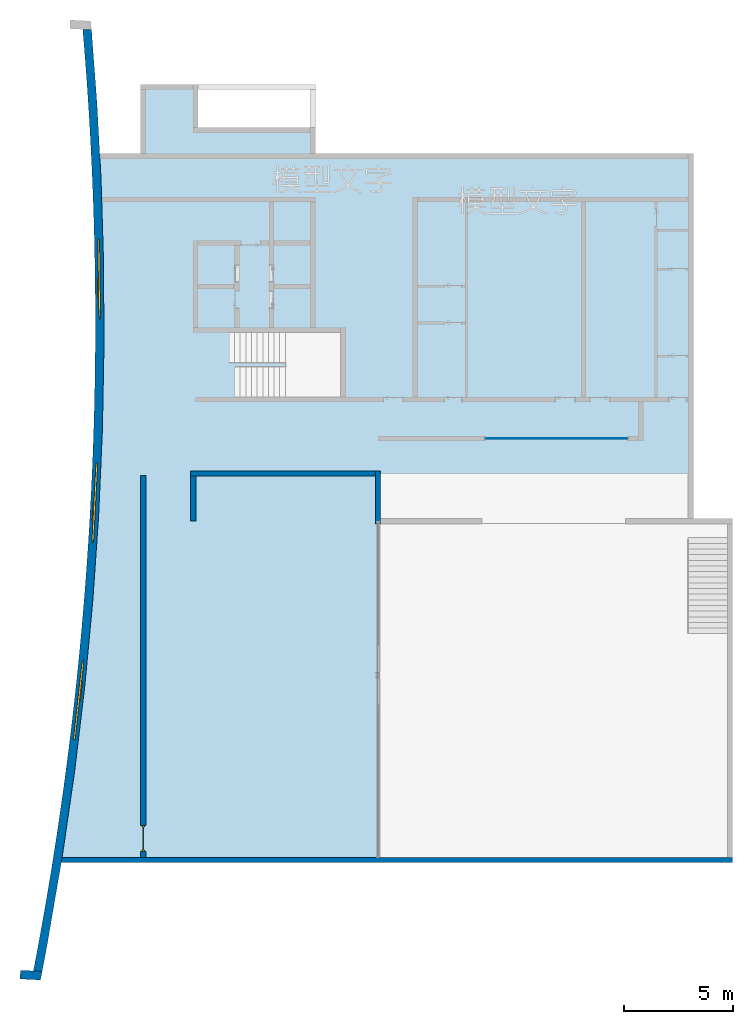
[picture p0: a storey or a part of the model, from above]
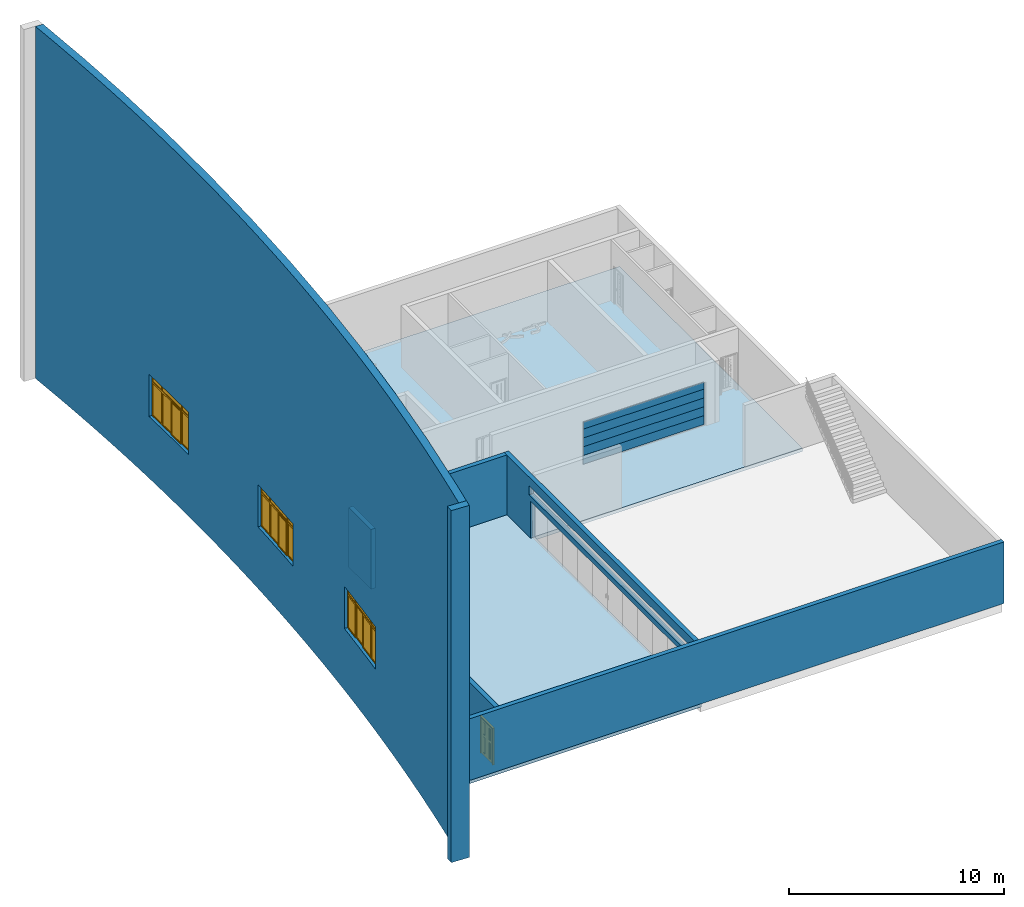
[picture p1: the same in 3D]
Properties of the parts of a building model (IFC2X3), part 1 of 2

# File
Description: ViewDefinition [CoordinationView_V2.0]
File name: 项目编号
Time: 2021-07-08T13:14:33
Written by: The EXPRESS Data Manager Version 5.02.0100.07 : 28 Aug 2013
Made in: 20180216_1515(x64) - Exporter 19.0.0.405 - 备用 UI 19.0.0.405
Comment: STEP Physical File produced by: The EXPRESS Data Manager Version 5.02.0100.07 : 28 Aug 2013 * Module: EDMstepFileFactory/EDMstandAlone * Creation date: Thu Jul 08 13:14:33 2021 * Host: DESKTOP-OMQ10H7 * Database: C:\Users\12580\AppData\Local\Temp\{74D62C54-28BB-4BCD-B5E0-11592904E337}\ifc * Database version: 5507 * Database creation date: Thu Jul 08 13:13:54 2021 * Schema: IFC2X3 * Model: DataRepository.ifc * Model creation date: Thu Jul 08 13:13:54 2021 * Header model: DataRepository.ifc_HeaderModel * Header model creation date: Thu Jul 08 13:13:54 2021 * EDMuser: sdai-user * EDMgroup: sdai-group * License ID and type: 5605 : Permanent license. Expiry date: * EDMstepFileFactory options: 020000

# IfcProject, 项目编号
LongName: 项目名称; Phase: 项目状态

# IfcSite, 表面:545270
RefLatitude: 42, 23, 13, 199999; RefLongitude: -71, -14, -31, -199999; RefElevation: 0 mm

# IfcBuilding
Pset_BuildingCommon - NumberOfStoreys: 6

# IfcBuildingStorey (6)
Name | LongName | Elevation (mm)
-1F | -1F | -3500
室外地坪 | 室外地坪 | -450
1F | 1F | 0
2F | 2F | 3000
3F | 3F | 6000
4F | 4F | 9000

# IfcBuildingElementProxy: 1 (2)
In: 1F
Type - Material: 默认体量
Pset_BuildingElementProxyCommon - Reference: 1
Name
1:1:349102
4:1:356210

# IfcBuildingElementProxy: 1800 mm (41)
Material: 木质 - 柚木, 金属 - 油漆面层 - 深灰色，粗面
Pset_BuildingElementProxyCommon - Reference: 1800 mm
Name (长椅:1800 mm:...) | In | Group
541240 | 1F | 模型组:长椅:541651
541490 | 1F | 模型组:长椅:541651
541573 | 1F | 模型组:长椅:541651
541606 | 1F | 模型组:长椅:541651
541667 | 1F | 模型组:长椅:541671
541668 | 1F | 模型组:长椅:541671
541669 | 1F | 模型组:长椅:541671
541670 | 1F | 模型组:长椅:541671
541781 | 1F | 模型组:长椅:541785
541782 | 1F | 模型组:长椅:541785
541783 | 1F | 模型组:长椅:541785
541784 | 1F | 模型组:长椅:541785
541787 | 1F | 模型组:长椅:541791
541788 | 1F | 模型组:长椅:541791
541789 | 1F | 模型组:长椅:541791
541790 | 1F | 模型组:长椅:541791
541793 | 1F | 模型组:长椅:541797
541794 | 1F | 模型组:长椅:541797
541795 | 1F | 模型组:长椅:541797
541796 | 1F | 模型组:长椅:541797
541799 | 1F | 模型组:长椅:541803
541800 | 1F | 模型组:长椅:541803
541801 | 1F | 模型组:长椅:541803
541802 | 1F | 模型组:长椅:541803
541805 | 1F | 模型组:长椅:541809
541806 | 1F | 模型组:长椅:541809
541807 | 1F | 模型组:长椅:541809
541808 | 1F | 模型组:长椅:541809
541811 | 1F | 模型组:长椅:541815
541812 | 1F | 模型组:长椅:541815
541813 | 1F | 模型组:长椅:541815
541814 | 1F | 模型组:长椅:541815
541817 | 1F | 模型组:长椅:541821
541818 | 1F | 模型组:长椅:541821
541819 | 1F | 模型组:长椅:541821
541820 | 1F | 模型组:长椅:541821
541823 | 1F | 模型组:长椅:541827
541824 | 1F | 模型组:长椅:541827
541825 | 1F | 模型组:长椅:541827
541826 | 1F | 模型组:长椅:541827
547560 | 室外地坪

# IfcBuildingElementProxy: 2 (2)
In: 1F
Type - Material: 默认体量
Pset_BuildingElementProxyCommon - Reference: 2
Name
2:2:351852
5:2:357694

# IfcBuildingElementProxy: 3 (2)
In: 1F
Type - Material: 默认体量
Pset_BuildingElementProxyCommon - Reference: 3
Name
3:3:354207
6:3:358945

# IfcBuildingElementProxy: Alex (3)
In: 室外地坪
Pset_BuildingElementProxyCommon - Reference: Alex
Name (RPC 男性:Alex:...)
560207
560258
560286

# IfcBuildingElementProxy: Cathy, RPC 女性:Cathy:559751
In: 室外地坪
Pset_BuildingElementProxyCommon - Reference: Cathy

# IfcBuildingElementProxy: RPC 甲虫, RPC 甲虫:RPC 甲虫:559956
In: 室外地坪
Pset_BuildingElementProxyCommon - Reference: RPC 甲虫

# IfcBuildingElementProxy: 中部体量, 中部体量:中部体量:361719
In: 1F
Type - Material: 默认体量
Pset_BuildingElementProxyCommon - Reference: 中部体量

# IfcBuildingElementProxy: 佛罗伦萨 (3)
In: 室外地坪
Pset_BuildingElementProxyCommon - Reference: 佛罗伦萨
Name (RPC 女性:佛罗伦萨:...)
559883
559900
559914

# IfcBuildingElementProxy: 公园长椅 2, 公园长椅 2:公园长椅 2:557213
In: 室外地坪
Material: 木质座椅, 预制混凝土
Pset_BuildingElementProxyCommon - Reference: 公园长椅 2

# IfcBuildingElementProxy: 北部体量, 北部体量:北部体量:362551
In: 1F
Type - Material: 默认体量
Pset_BuildingElementProxyCommon - Reference: 北部体量

# IfcBuildingElementProxy: 模型文字:600mm Arial (3)
Pset_BuildingElementProxyCommon - Reference: 600mm Arial
Name (模型文字:...) | In
2 x 600mm Arial | -1F
600mm Arial | 2F

# IfcBuildingElementProxy: 混凝土卡车 (2)
In: 室外地坪
Material: 金属-钢, 塑料 - 黑色, 金属 - 铬板, 金属 - 油漆面层 - 白色，粗面
Pset_BuildingElementProxyCommon - Reference: 混凝土卡车
Name (混凝土卡车:混凝土卡车:...)
549684
560604

# IfcColumn: 300 x 300mm (2)
In: 1F
Type - ElementType: 300 x 300mm; PredefinedType: COLUMN
Material: 柱
Pset_ColumnCommon - LoadBearing: no; IsExternal: no; Reference: 300 x 300mm; Slope: 0 deg
Name (矩形柱:300 x 300mm:...)
490802
491124

# IfcCurtainWall: 幕墙:幕墙 1 (9)
Pset_CurtainWallCommon - IsExternal: yes; Reference: 幕墙 1
Name (幕墙:幕墙 1:...) | In
402175 | 1F
402436 | 1F
407601 | 2F
407627 | 2F
427601 | 3F
432666 | 1F
434830 | -1F
437507 | -1F
528400 | 4F

# IfcCurtainWall: 幕墙:幕墙 2 (10)
Pset_CurtainWallCommon - IsExternal: yes; Reference: 幕墙 2
Name (幕墙:幕墙 2:...) | In
402656 | 1F
402850 | 1F
403013 | 1F
407659 | 3F
407665 | 3F
408702 | 2F
434038 | 1F
438280 | 2F
439420 | 3F
439495 | 3F

# IfcCurtainWall: 幕墙:幕墙 4 (8)
Pset_CurtainWallCommon - IsExternal: no; Reference: 幕墙 4
Name (幕墙:幕墙 4:...) | In
427907 | 3F
428382 | 3F
428785 | 3F
429204 | 3F
429508 | 3F
429925 | 2F
430066 | 2F
430233 | 2F

# IfcCurtainWall: 幕墙:幕墙 5, 幕墙:幕墙 5:432943
In: 1F
Pset_CurtainWallCommon - IsExternal: yes; Reference: 幕墙 5

# IfcCurtainWall: 幕墙:店面 (2)
Pset_CurtainWallCommon - IsExternal: yes; Reference: 店面
Name (幕墙:店面:...) | In
420110 | 3F
437167 | -1F

# IfcCurtainWall: 幕墙系统:1450 x 2100mm (6)
Pset_CurtainWallCommon - Reference: 1450 x 2100mm; IsExternal: no
Name (幕墙系统:1450 x 2100mm:...) | In
362911 | 1F
370759 | 1F
370957 | 1F
470212 | 1F
471675 | 1F
473225 | 3F

# IfcCurtainWall: 幕墙系统:1700 x 2100mm, 幕墙系统:1700 x 2100mm:366782
In: 3F
Pset_CurtainWallCommon - IsExternal: no; Reference: 1700 x 2100mm

# IfcDoor: 1200 x 2100 mm, 门-双扇平开:1200 x 2100 mm:384247
In: -1F
Type - OperationType: DOUBLE_DOOR_SINGLE_SWING; ParameterTakesPrecedence: no; Sizeable: no
Type - 门-双扇平开:1200 x 2100 mm:384247 - PanelOperation: SWINGING
OverallHeight: 2100 mm; OverallWidth: 1200 mm
Pset_DoorCommon - IsExternal: no; Reference: 1200 x 2100 mm

# IfcDoor: M0821 (26)
Type - ParameterTakesPrecedence: no; Sizeable: no; Material: 不锈钢, 门框材质, 门套材质, 门板材质
OverallHeight: 2100 mm; OverallWidth: 800 mm
Pset_DoorCommon - IsExternal: no; Reference: M0821
Name (装饰木门:M0821:...) | In
382676 | -1F
382819 | -1F
383177 | -1F
383178 | -1F
383197 | -1F
383379 | -1F
383451 | -1F
383554 | -1F
383631 | -1F
383688 | -1F
383731 | -1F
396554 | 1F
396845 | 1F
396930 | 1F
396993 | 1F
397054 | 1F
407593 | 2F
407594 | 2F
407595 | 2F
407596 | 2F
407597 | 2F
425033 | 3F
425121 | 3F
425207 | 3F
425580 | 3F
425584 | 3F

# IfcDoor: M0921 (16)
Type - ParameterTakesPrecedence: no; Sizeable: no; Material: 门锁－不锈钢, 门框材质, 门套材质, 门板材质
OverallHeight: 2100 mm; OverallWidth: 900 mm
Pset_DoorCommon - IsExternal: no; Reference: M0921
Name (装饰木门:M0921:...) | In
382155 | -1F
382442 | -1F
383980 | -1F
384059 | -1F
396196 | 1F
396287 | 1F
397109 | 1F
397167 | 1F
397294 | 1F
397396 | 1F
407598 | 2F
407599 | 2F
424080 | 3F
424512 | 3F
424859 | 3F
424940 | 3F

# IfcDoor: YM3267 (3)
In: 1F
Type - ParameterTakesPrecedence: no; Sizeable: no; Material: 玻璃, 铝合金
OverallHeight: 2400 mm; OverallWidth: 1800 mm
Pset_DoorCommon - IsExternal: no; Reference: YM3267
Name (YM1824:YM3267:...)
493118
493990
494000

# IfcDoor: YM3624 (6)
In: 1F
Type - ParameterTakesPrecedence: no; Sizeable: no; Material: 铝合金, 玻璃
OverallHeight: 2400 mm; OverallWidth: 3600 mm
Pset_DoorCommon - IsExternal: no; Reference: YM3624
Name (YM3627:YM3624:...)
495469
495638
495714
495795
495809
495830

# IfcDoor: 幕墙单开玻璃门 900/2100 (2)
In: 3F
Type - OperationType: SINGLE_SWING_LEFT; ParameterTakesPrecedence: no; Sizeable: no; Material: 金属 - 铝, 玻璃
Type - 幕墙单开玻璃门:幕墙单开玻璃门 900/2100:428383 - PanelOperation: SWINGING
OverallHeight: 2050 mm; OverallWidth: 1400 mm
Pset_DoorCommon - IsExternal: no; Reference: 幕墙单开玻璃门 900/2100
Name (幕墙单开玻璃门:幕墙单开玻璃门 900/2100:...)
428383
429509

# IfcDoor: 幕墙单开玻璃门 900/2100, 幕墙单开玻璃门:幕墙单开玻璃门 900/2100:428786
In: 3F
Type - OperationType: SINGLE_SWING_LEFT; ParameterTakesPrecedence: no; Sizeable: no; Material: 金属 - 铝, 玻璃
Type - 幕墙单开玻璃门:幕墙单开玻璃门 900/2100:428786 - PanelOperation: SWINGING
OverallHeight: 2050 mm; OverallWidth: 1100 mm
Pset_DoorCommon - IsExternal: no; Reference: 幕墙单开玻璃门 900/2100

# IfcDoor: 幕墙单开玻璃门 900/2100, 幕墙单开玻璃门:幕墙单开玻璃门 900/2100:438494
In: 2F
Type - OperationType: SINGLE_SWING_LEFT; ParameterTakesPrecedence: no; Sizeable: no; Material: 金属 - 铝, 玻璃
Type - 幕墙单开玻璃门:幕墙单开玻璃门 900/2100:438494 - PanelOperation: SWINGING
OverallHeight: 2550 mm; OverallWidth: 1225 mm
Pset_DoorCommon - IsExternal: no; Reference: 幕墙单开玻璃门 900/2100

# IfcDoor: 幕墙单开玻璃门 900/2100, 幕墙单开玻璃门:幕墙单开玻璃门 900/2100:439426
In: 3F
Type - OperationType: SINGLE_SWING_LEFT; ParameterTakesPrecedence: no; Sizeable: no; Material: 金属 - 铝, 玻璃
Type - 幕墙单开玻璃门:幕墙单开玻璃门 900/2100:439426 - PanelOperation: SWINGING
OverallHeight: 2550 mm; OverallWidth: 1185 mm
Pset_DoorCommon - IsExternal: no; Reference: 幕墙单开玻璃门 900/2100

# IfcDoor: 幕墙单开玻璃门 900/2100, 幕墙单开玻璃门:幕墙单开玻璃门 900/2100:471819
In: 1F
Type - OperationType: SINGLE_SWING_LEFT; ParameterTakesPrecedence: no; Sizeable: no; Material: 金属 - 铝, 玻璃
Type - 幕墙单开玻璃门:幕墙单开玻璃门 900/2100:471819 - PanelOperation: SWINGING
OverallHeight: 1925 mm; OverallWidth: 1400 mm
Pset_DoorCommon - IsExternal: no; Reference: 幕墙单开玻璃门 900/2100

# IfcDoor: 幕墙单开玻璃门 900/2100, 幕墙单开玻璃门:幕墙单开玻璃门 900/2100:563182
In: -1F
Type - OperationType: SINGLE_SWING_LEFT; ParameterTakesPrecedence: no; Sizeable: no; Material: 金属 - 铝, 玻璃
Type - 幕墙单开玻璃门:幕墙单开玻璃门 900/2100:563182 - PanelOperation: SWINGING
OverallHeight: 2050 mm; OverallWidth: 1396.36 mm
Pset_DoorCommon - IsExternal: no; Reference: 幕墙单开玻璃门 900/2100

# IfcDoor: 幕墙单开玻璃门 900/2100 (2)
In: 3F
Type - OperationType: SINGLE_SWING_RIGHT; ParameterTakesPrecedence: no; Sizeable: no; Material: 金属 - 铝, 玻璃
Type - 幕墙单开玻璃门:幕墙单开玻璃门 900/2100:427908 - PanelOperation: SWINGING
OverallHeight: 2050 mm; OverallWidth: 1100 mm
Pset_DoorCommon - IsExternal: no; Reference: 幕墙单开玻璃门 900/2100
Name (幕墙单开玻璃门:幕墙单开玻璃门 900/2100:...)
427908
429205

# IfcDoor: 幕墙单开玻璃门 900/2100, 幕墙单开玻璃门:幕墙单开玻璃门 900/2100:563180
In: -1F
Type - OperationType: SINGLE_SWING_RIGHT; ParameterTakesPrecedence: no; Sizeable: no; Material: 金属 - 铝, 玻璃
Type - 幕墙单开玻璃门:幕墙单开玻璃门 900/2100:563180 - PanelOperation: SWINGING
OverallHeight: 2050 mm; OverallWidth: 1396.36 mm
Pset_DoorCommon - IsExternal: no; Reference: 幕墙单开玻璃门 900/2100

# IfcDoor: 幕墙双开玻璃门 1800/2100 (3)
In: 1F
Type - OperationType: DOUBLE_DOOR_SINGLE_SWING; ParameterTakesPrecedence: no; Sizeable: no; Material: 金属 - 铝, 玻璃
Type - 幕墙双开玻璃门:幕墙双开玻璃门 1800/2100:362931 - PanelOperation: SWINGING
OverallHeight: 1926.86 mm; OverallWidth: 2850 mm
Pset_DoorCommon - IsExternal: no; Reference: 幕墙双开玻璃门 1800/2100
Name (幕墙双开玻璃门:幕墙双开玻璃门 1800/2100:...)
362931
470527
470531

# IfcDoor: 幕墙双开玻璃门 1800/2100, 幕墙双开玻璃门:幕墙双开玻璃门 1800/2100:407660
In: 3F
Type - OperationType: DOUBLE_DOOR_SINGLE_SWING; ParameterTakesPrecedence: no; Sizeable: no; Material: 金属 - 铝, 玻璃
Type - 幕墙双开玻璃门:幕墙双开玻璃门 1800/2100:407660 - PanelOperation: SWINGING
OverallHeight: 2651.86 mm; OverallWidth: 1745 mm
Pset_DoorCommon - IsExternal: no; Reference: 幕墙双开玻璃门 1800/2100

# IfcDoor: 幕墙双开玻璃门 1800/2100, 幕墙双开玻璃门:幕墙双开玻璃门 1800/2100:407666
In: 3F
Type - OperationType: DOUBLE_DOOR_SINGLE_SWING; ParameterTakesPrecedence: no; Sizeable: no; Material: 金属 - 铝, 玻璃
Type - 幕墙双开玻璃门:幕墙双开玻璃门 1800/2100:407666 - PanelOperation: SWINGING
OverallHeight: 2651.86 mm; OverallWidth: 2460 mm
Pset_DoorCommon - IsExternal: no; Reference: 幕墙双开玻璃门 1800/2100

# IfcDoor: 幕墙双开玻璃门 1800/2100, 幕墙双开玻璃门:幕墙双开玻璃门 1800/2100:434039
In: 1F
Type - OperationType: DOUBLE_DOOR_SINGLE_SWING; ParameterTakesPrecedence: no; Sizeable: no; Material: 金属 - 铝, 玻璃
Type - 幕墙双开玻璃门:幕墙双开玻璃门 1800/2100:434039 - PanelOperation: SWINGING
OverallHeight: 2551.86 mm; OverallWidth: 2180 mm
Pset_DoorCommon - IsExternal: no; Reference: 幕墙双开玻璃门 1800/2100

# IfcDoor: 幕墙双开玻璃门 1800/2100, 幕墙双开玻璃门:幕墙双开玻璃门 1800/2100:435355
In: 3F
Type - OperationType: DOUBLE_DOOR_SINGLE_SWING; ParameterTakesPrecedence: no; Sizeable: no; Material: 金属 - 铝, 玻璃
Type - 幕墙双开玻璃门:幕墙双开玻璃门 1800/2100:435355 - PanelOperation: SWINGING
OverallHeight: 2651.86 mm; OverallWidth: 2065 mm
Pset_DoorCommon - IsExternal: no; Reference: 幕墙双开玻璃门 1800/2100

# IfcDoor: 幕墙双开玻璃门 1800/2100, 幕墙双开玻璃门:幕墙双开玻璃门 1800/2100:530989
In: 3F
Type - OperationType: DOUBLE_DOOR_SINGLE_SWING; ParameterTakesPrecedence: no; Sizeable: no; Material: 金属 - 铝, 玻璃
Type - 幕墙双开玻璃门:幕墙双开玻璃门 1800/2100:530989 - PanelOperation: SWINGING
OverallHeight: 2376.86 mm; OverallWidth: 2580 mm
Pset_DoorCommon - IsExternal: no; Reference: 幕墙双开玻璃门 1800/2100

# IfcMember: 200 x 150mm (378)
Type - ElementType: 200 x 150mm; PredefinedType: MEMBER
Material: 木质 - 木材
Pset_MemberCommon - IsExternal: no; LoadBearing: yes; Reference: 200 x 150mm
Name (矩形竖梃:200 x 150mm:...) | In | Span (mm)
363015 | 1F | 971.063
363016 | 1F | 412.198
363017 | 1F | 1501.01
363018 | 1F | 1501.01
363019 | 1F | 2105.22
363020 | 1F | 2116.63
363021 | 1F | 2131
363022 | 1F | 2151.01
363023 | 1F | 127.533
363024 | 1F | 1054.05
363025 | 1F | 2100.82
363026 | 1F | 2107.41
363027 | 1F | 2120.79
363028 | 1F | 2141.35
363142 | 1F | 280
363143 | 1F | 1425
363144 | 1F | 1236.66
363145 | 1F | 202.271
480478 | 1F | 1425
480479 | 1F | 1236.66
363042 | 1F | 412.924
363043 | 1F | 1425
363044 | 1F | 527.766
363045 | 1F | 1501.01
363046 | 1F | 2101.27
363047 | 1F | 2111.51
363048 | 1F | 2132.46
363049 | 1F | 1211.51
363050 | 1F | 350.213
363051 | 1F | 2106.56
363052 | 1F | 2122.27
363053 | 1F | 2141.38
363164 | 1F | 1400
363165 | 1F | 1223.42
366785 | 3F | 628.845
366786 | 3F | 1513.49
366787 | 3F | 2102.69
366788 | 3F | 1018
366904 | 3F | 1906.11
366905 | 3F | 253.002
366906 | 3F | 1968.35
366907 | 3F | 1912.8
366908 | 3F | 1568.41
366909 | 3F | 1828.98
366910 | 3F | 1796.37
366911 | 3F | 844.641
366912 | 3F | 1748.78
366913 | 3F | 1732.03
366914 | 3F | 1786.38
366915 | 3F | 301.544
366916 | 3F | 928.231
366917 | 3F | 2082.13
366918 | 3F | 915.346
366919 | 3F | 1947.33
366920 | 3F | 1286.7
366921 | 3F | 1853.18
366922 | 3F | 1817.18
366923 | 3F | 1470.92
366924 | 3F | 1762.36
366925 | 3F | 1742.24
366926 | 3F | 413.468
366927 | 3F | 658.268
366928 | 3F | 1093.35
366929 | 3F | 609.558
366930 | 3F | 316.31
366931 | 3F | 1149.51
366932 | 3F | 1117.99
366933 | 3F | 2102.69
370762 | 1F | 813.114
370763 | 1F | 1164.71
370764 | 1F | 2100
370765 | 1F | 313.218
370790 | 1F | 813.114
370791 | 1F | 1164.71
370792 | 1F | 2100
370793 | 1F | 2100
370794 | 1F | 2100
370795 | 1F | 1546.41
370796 | 1F | 2100
370797 | 1F | 2100
370798 | 1F | 2100
370799 | 1F | 2100
370960 | 1F | 525.869
370961 | 1F | 277.654
370962 | 1F | 460.207
370963 | 1F | 2100
371001 | 1F | 1275
371003 | 1F | 1709.15
371005 | 1F | 2100
371006 | 1F | 2100
371007 | 1F | 2100
371008 | 1F | 1953.01
371009 | 1F | 460.207
371010 | 1F | 2100
371011 | 1F | 2100
371012 | 1F | 2100
371013 | 1F | 2100
371100 | 1F | 1400
371106 | 1F | 826.132
371258 | 1F | 1431.5
470223 | 1F | 900.327
470224 | 1F | 1720.07
470225 | 1F | 2102.07
470226 | 1F | 772.514
470978 | 1F | 1060.92
470979 | 1F | 1452.77
470980 | 1F | 1452.77
470981 | 1F | 1452.77
470982 | 1F | 1452.77
470983 | 1F | 1452.77
470984 | 1F | 1452.77
470985 | 1F | 1452.77
470986 | 1F | 1452.77
470987 | 1F | 1452.77
470988 | 1F | 1452.77
470989 | 1F | 1452.77
470990 | 1F | 1452.77
470991 | 1F | 1452.77
470992 | 1F | 1452.77
470993 | 1F | 1452.77
470994 | 1F | 1452.77
470995 | 1F | 1452.77
470996 | 1F | 1452.77
470997 | 1F | 1452.77
470998 | 1F | 1452.77
470999 | 1F | 1552.03
471000 | 1F | 1631.03
471001 | 1F | 1596.03
471002 | 1F | 1566.11
471003 | 1F | 103.6
471004 | 1F | 1518.94
471005 | 1F | 1500.74
471006 | 1F | 1485.67
471007 | 1F | 1473.48
471008 | 1F | 1378.06
471009 | 1F | 1456.98
471010 | 1F | 1452.43
471011 | 1F | 1450.23
471012 | 1F | 1450.36
471013 | 1F | 1452.82
471014 | 1F | 1380.29
471015 | 1F | 1464.9
471016 | 1F | 1474.71
471017 | 1F | 1487.21
471018 | 1F | 1502.61
471019 | 1F | 406.519
471020 | 1F | 119.992
471021 | 1F | 1437.01
471022 | 1F | 85.9248
471023 | 1F | 77.3687
471024 | 1F | 2102.07
471025 | 1F | 2102.07
471026 | 1F | 2102.07
471027 | 1F | 400.107
471028 | 1F | 187.068
471029 | 1F | 2102.07
471030 | 1F | 2102.07
471031 | 1F | 2102.07
471032 | 1F | 2102.07
471033 | 1F | 2102.07
470219 | 1F | 406.676
470220 | 1F | 1050.25
470221 | 1F | 2100
470222 | 1F | 805.488
470801 | 1F | 1275
470802 | 1F | 1400
470803 | 1F | 1425
470804 | 1F | 1425
470805 | 1F | 1425
470806 | 1F | 1425
470807 | 1F | 1400
470808 | 1F | 1400
470809 | 1F | 1400
470810 | 1F | 1400
470811 | 1F | 1709.15
470812 | 1F | 1598.73
470813 | 1F | 1709.15
470814 | 1F | 1709.15
470815 | 1F | 438.06
470816 | 1F | 1215.04
470817 | 1F | 658.896
470818 | 1F | 110.418
470819 | 1F | 1271.09
470820 | 1F | 2100
470821 | 1F | 2100
470822 | 1F | 2100
470823 | 1F | 2100
470824 | 1F | 1544
470825 | 1F | 726.09
470826 | 1F | 716.816
470827 | 1F | 1225.07
470828 | 1F | 2100.99
470829 | 1F | 2109
470830 | 1F | 900.467
470831 | 1F | 2150.44
470832 | 1F | 2185.42
470833 | 1F | 1515.08
470834 | 1F | 2291.18
470835 | 1F | 2352.8
470228 | 1F | 919.197
470229 | 1F | 1119.2
470230 | 1F | 92.6751
470231 | 1F | 2101.21
470232 | 1F | 2100
470233 | 1F | 530.201
470234 | 1F | 650
470761 | 1F | 330.803
470762 | 1F | 1400
470763 | 1F | 130.803
470764 | 1F | 1400
470765 | 1F | 1400
470766 | 1F | 1400
470767 | 1F | 1425
470768 | 1F | 1400
470769 | 1F | 1773.28
470771 | 1F | 1709.15
470772 | 1F | 623.011
470773 | 1F | 1709.15
470774 | 1F | 169.969
470775 | 1F | 1086.14
470776 | 1F | 1827.77
470777 | 1F | 1198.77
470778 | 1F | 1808.57
470779 | 1F | 2110.96
470780 | 1F | 2130.89
470781 | 1F | 2161.86
470782 | 1F | 1006.93
470783 | 1F | 2263.59
470784 | 1F | 531.709
470785 | 1F | 1140.14
470786 | 1F | 2100
470787 | 1F | 2100
470788 | 1F | 2100
470789 | 1F | 2100
470790 | 1F | 650
470791 | 1F | 2100
470792 | 1F | 2100
470793 | 1F | 2100
470794 | 1F | 2100
470795 | 1F | 2100
470796 | 1F | 2100
470797 | 1F | 2100
470798 | 1F | 2100
470799 | 1F | 2100
470800 | 1F | 2100
471690 | 1F | 94.8808
471691 | 1F | 1179.71
471692 | 1F | 2102.55
471693 | 1F | 576.865
471962 | 1F | 1529.01
471963 | 1F | 1690.04
471964 | 1F | 787.746
471965 | 1F | 1610.45
471966 | 1F | 1579.66
471967 | 1F | 291.576
471968 | 1F | 1529.13
471969 | 1F | 1511.27
471970 | 1F | 1495.34
471971 | 1F | 1482.37
471972 | 1F | 1472.14
471973 | 1F | 1464.5
471974 | 1F | 1459.33
471975 | 1F | 1456.56
471976 | 1F | 1456.14
471977 | 1F | 1456.65
471978 | 1F | 862.118
471979 | 1F | 1263.26
471980 | 1F | 1738.08
471981 | 1F | 1527.45
471982 | 1F | 1644.5
471983 | 1F | 1607.72
471984 | 1F | 1396.31
471985 | 1F | 1549.36
471986 | 1F | 1526.47
471987 | 1F | 1507.14
471988 | 1F | 1491.01
471989 | 1F | 1283.74
471990 | 1F | 1467.35
471991 | 1F | 1459.44
471992 | 1F | 1453.96
471993 | 1F | 1450.84
471994 | 1F | 1304.13
471995 | 1F | 618.239
471996 | 1F | 160.123
471997 | 1F | 179.98
471998 | 1F | 194.121
471999 | 1F | 1396.2
472000 | 1F | 1816.18
472001 | 1F | 107.448
472002 | 1F | 286.364
472003 | 1F | 2102.55
471686 | 1F | 675.136
471687 | 1F | 1542.81
471688 | 1F | 2105.29
471689 | 1F | 1169.29
472041 | 1F | 1400
472042 | 1F | 1400
472043 | 1F | 1400
472044 | 1F | 85.8522
472045 | 1F | 1542.81
472046 | 1F | 260.971
472047 | 1F | 1456.96
472048 | 1F | 2116.91
472049 | 1F | 2131.63
472050 | 1F | 2153.68
472051 | 1F | 1600.36
472052 | 1F | 814.638
472053 | 1F | 2100.88
472054 | 1F | 2107.93
472055 | 1F | 2122.26
472056 | 1F | 1329.9
472057 | 1F | 2174.82
471682 | 1F | 749.617
471684 | 1F | 2101.29
471685 | 1F | 1433.97
472004 | 1F | 1425
472005 | 1F | 1400
472006 | 1F | 1569.41
472007 | 1F | 212.275
472008 | 1F | 350.885
472009 | 1F | 1330.54
472010 | 1F | 2111.74
472011 | 1F | 2133.1
472012 | 1F | 2166.4
472013 | 1F | 648.889
472014 | 1F | 134.916
472015 | 1F | 2106.31
472016 | 1F | 2121.21
472017 | 1F | 2138.77
473228 | 3F | 670.971
473229 | 3F | 1452.55
473230 | 3F | 2102.07
473350 | 3F | 1321.57
473351 | 3F | 1400
473352 | 3F | 1400
473353 | 3F | 1400
473354 | 3F | 1400
473355 | 3F | 1400
473356 | 3F | 1400
473357 | 3F | 1400
473358 | 3F | 1400
473359 | 3F | 1400
473360 | 3F | 1400
473361 | 3F | 1400
473362 | 3F | 1400
473363 | 3F | 1400
473364 | 3F | 1400
473365 | 3F | 1400
473366 | 3F | 1400
473367 | 3F | 1400
473368 | 3F | 1400
473369 | 3F | 1400
473370 | 3F | 1400
473371 | 3F | 1452.68
473372 | 3F | 1452.17
473373 | 3F | 1451.82
473374 | 3F | 1451.65
473375 | 3F | 1451.65
473376 | 3F | 1451.82
473377 | 3F | 1452.15
473378 | 3F | 1452.67
473379 | 3F | 1453.35
473380 | 3F | 1454.2
473381 | 3F | 1455.23
473382 | 3F | 1456.42
473383 | 3F | 1457.8
473384 | 3F | 1459.34
473385 | 3F | 1461.07
473386 | 3F | 1462.97
473387 | 3F | 1465.04
473388 | 3F | 1467.3
473389 | 3F | 1469.74
473390 | 3F | 1472.03
473391 | 3F | 286.835
473392 | 3F | 229.366
473393 | 3F | 227.356
473394 | 3F | 2102.07
473395 | 3F | 2127.1

# IfcMember: 300x600 (16)
In: 1F
Type - ElementType: 300x600; PredefinedType: MEMBER
Material: 白色涂料
Pset_MemberCommon - IsExternal: yes; LoadBearing: yes; Reference: 300x600
Name (矩形竖梃:300x600:...) | Span (mm)
488811 | 5150
488812 | 1690
488813 | 1690
490039 | 5150
490212 | 1540
490213 | 1540
490214 | 1540
490215 | 1690
490217 | 1690
490218 | 1540
490219 | 1540
490220 | 1540
490237 | 5150
490241 | 5150
490245 | 5150
490249 | 5150

# IfcMember: 30mm 正方形 (5)
Type - ElementType: 30mm 正方形; PredefinedType: MEMBER
Material: 金属 - 铝
Pset_MemberCommon - IsExternal: yes; LoadBearing: yes; Reference: 30mm 正方形
Name (矩形竖梃:30mm 正方形:...) | In | Span (mm)
563247 | -1F | 2100
500285 | 1F | 900
500373 | 1F | 900
489527 | 1F | 900
489552 | 1F | 900

# IfcMember: 50 x 100mm (874)
Type - ElementType: 50 x 100mm; PredefinedType: MEMBER
Material: 金属 - 铝
Pset_MemberCommon - LoadBearing: yes; Reference: 50 x 100mm
Name (矩形竖梃:50 x 100mm:...) | In | IsExternal | Span (mm)
363029 | 1F | no | 472.865
363030 | 1F | no | 1400
363031 | 1F | no | 655.474
363033 | 1F | no | 961.892
363034 | 1F | no | 1400
363035 | 1F | no | 1395.33
363036 | 1F | no | 1400
363037 | 1F | no | 512.028
363038 | 1F | no | 2100
363039 | 1F | no | 2100
363040 | 1F | no | 2100
363041 | 1F | no | 2100
363146 | 1F | no | 1400
363147 | 1F | no | 912.372
363149 | 1F | no | 735.744
363150 | 1F | no | 1400
363151 | 1F | no | 439.493
363152 | 1F | no | 1400
363153 | 1F | no | 20.7201
363154 | 1F | no | 900.022
363155 | 1F | no | 197.036
363157 | 1F | no | 2100
363158 | 1F | no | 2125
363159 | 1F | no | 2100
363161 | 1F | no | 2100
363162 | 1F | no | 2125
363163 | 1F | no | 2100
480480 | 1F | no | 255
480482 | 1F | no | 255
480483 | 1F | no | 255
480596 | 1F | no | 900.022
480597 | 1F | no | 2125
480598 | 1F | no | 2100
480603 | 1F | no | 2100
480882 | 1F | no | 1400
480884 | 1F | no | 1400
363054 | 1F | no | 1351.95
363055 | 1F | no | 1400
363056 | 1F | no | 1131.74
363057 | 1F | no | 1400
363058 | 1F | no | 761.074
363059 | 1F | no | 1400
363060 | 1F | no | 1043.18
363061 | 1F | no | 2100
363062 | 1F | no | 2100
363063 | 1F | no | 2100
363166 | 1F | no | 486.525
363167 | 1F | no | 708.42
363168 | 1F | no | 1081.98
363169 | 1F | no | 655.181
363170 | 1F | no | 2100
363171 | 1F | no | 2100
363172 | 1F | no | 2100
366934 | 3F | no | 1616.88
366935 | 3F | no | 1463.43
366936 | 3F | no | 498.387
366937 | 3F | no | 1650
366938 | 3F | no | 1650
366939 | 3F | no | 1650
366940 | 3F | no | 244.094
366941 | 3F | no | 907.359
366942 | 3F | no | 1650
366943 | 3F | no | 1650
366944 | 3F | no | 1650
366945 | 3F | no | 1650
366946 | 3F | no | 862.393
366947 | 3F | no | 526.005
366948 | 3F | no | 1650
366949 | 3F | no | 1650
366950 | 3F | no | 1650
366951 | 3F | no | 1650
366952 | 3F | no | 1650
366953 | 3F | no | 538.625
366954 | 3F | no | 277.718
366955 | 3F | no | 1650
366956 | 3F | no | 1650
366957 | 3F | no | 432.319
366958 | 3F | no | 399.229
366959 | 3F | no | 1601.42
366960 | 3F | no | 571.069
366961 | 3F | no | 1520.85
366962 | 3F | no | 260.68
366963 | 3F | no | 998.437
366964 | 3F | no | 1640.43
366965 | 3F | no | 91.7251
366966 | 3F | no | 556.403
366967 | 3F | no | 937.706
366968 | 3F | no | 977.124
366969 | 3F | no | 2100
366970 | 3F | no | 1969.38
366971 | 3F | no | 989.661
366972 | 3F | no | 126.551
366973 | 3F | no | 2100
366974 | 3F | no | 2100
366975 | 3F | no | 1471.09
366976 | 3F | no | 816.186
366977 | 3F | no | 256.173
366978 | 3F | no | 2100
366979 | 3F | no | 2100
366980 | 3F | no | 2100
366981 | 3F | no | 1886.55
366982 | 3F | no | 1503.76
366983 | 3F | no | 1205.03
366984 | 3F | no | 2100
366985 | 3F | no | 2100
366986 | 3F | no | 2100
370800 | 1F | no | 813.114
370801 | 1F | no | 813.114
370802 | 1F | no | 813.114
370803 | 1F | no | 813.114
370804 | 1F | no | 813.114
370805 | 1F | no | 813.114
370806 | 1F | no | 813.114
370807 | 1F | no | 813.114
370808 | 1F | no | 929.814
370809 | 1F | no | 2100
370810 | 1F | no | 2100
370811 | 1F | no | 2100
370812 | 1F | no | 2100
371016 | 1F | no | 1400
371019 | 1F | no | 1400
371022 | 1F | no | 1400
371025 | 1F | no | 1400
371030 | 1F | no | 460.207
371032 | 1F | no | 2100
371034 | 1F | no | 2100
371036 | 1F | no | 2100
371082 | 1F | no | 757.83
371101 | 1F | no | 525.869
371102 | 1F | no | 525.869
371103 | 1F | no | 525.869
371104 | 1F | no | 525.869
371105 | 1F | no | 525.869
371108 | 1F | no | 460.207
371109 | 1F | no | 2100
371110 | 1F | no | 2100
371111 | 1F | no | 2100
371146 | 1F | no | 1275
371147 | 1F | no | 1275
371148 | 1F | no | 1275
371149 | 1F | no | 1275
371233 | 1F | no | 1400
371234 | 1F | no | 2100
371259 | 1F | no | 1662.65
371289 | 1F | no | 1189.45
371290 | 1F | no | 2100
435362 | 3F | yes | 2700
531047 | 3F | yes | 1290
531048 | 3F | yes | 1290
531049 | 3F | yes | 1290
427920 | 3F | no | 1100
428395 | 3F | no | 1400
428798 | 3F | no | 1100
429217 | 3F | no | 1100
429518 | 3F | no | 1400
429938 | 2F | no | 1900
430079 | 2F | no | 3200
430246 | 2F | no | 2100
432967 | 1F | yes | 1180
432968 | 1F | yes | 1180
432969 | 1F | yes | 1180
432970 | 1F | yes | 1180
438501 | 2F | yes | 900
438892 | 2F | yes | 1650
439428 | 3F | yes | 900
439434 | 3F | yes | 1650
471034 | 1F | no | 1127.24
471035 | 1F | no | 1400
471036 | 1F | no | 1400
471037 | 1F | no | 1400
471038 | 1F | no | 1400
471039 | 1F | no | 1400
471040 | 1F | no | 1400
471041 | 1F | no | 1400
471042 | 1F | no | 1400
471043 | 1F | no | 1400
471044 | 1F | no | 1400
471045 | 1F | no | 1400
471046 | 1F | no | 1400
471047 | 1F | no | 1400
471048 | 1F | no | 1400
471049 | 1F | no | 1400
471050 | 1F | no | 1400
471051 | 1F | no | 1400
471052 | 1F | no | 1400
471053 | 1F | no | 1400
471054 | 1F | no | 1400
471055 | 1F | no | 865.307
471056 | 1F | no | 1220.57
471057 | 1F | no | 1400
471058 | 1F | no | 1400
471059 | 1F | no | 1400
471060 | 1F | no | 1400
471061 | 1F | no | 1400
471062 | 1F | no | 1400
471063 | 1F | no | 1400
471064 | 1F | no | 1400
471065 | 1F | no | 1400
471066 | 1F | no | 1400
471067 | 1F | no | 1400
471068 | 1F | no | 1400
471069 | 1F | no | 1400
471070 | 1F | no | 1400
471071 | 1F | no | 1400
471072 | 1F | no | 1400
471073 | 1F | no | 1400
471074 | 1F | no | 1400
471075 | 1F | no | 1400
471076 | 1F | no | 1400
471077 | 1F | no | 771.974
471078 | 1F | no | 1313.9
471079 | 1F | no | 1400
471080 | 1F | no | 1400
471081 | 1F | no | 1400
471082 | 1F | no | 1400
471083 | 1F | no | 1400
471084 | 1F | no | 1400
471085 | 1F | no | 1400
471086 | 1F | no | 1400
471087 | 1F | no | 1400
471088 | 1F | no | 1400
471089 | 1F | no | 1400
471090 | 1F | no | 1400
471091 | 1F | no | 1400
471092 | 1F | no | 1400
471093 | 1F | no | 1400
471094 | 1F | no | 1400
471095 | 1F | no | 1400
471096 | 1F | no | 1400
471097 | 1F | no | 1400
471098 | 1F | no | 1400
471099 | 1F | no | 678.641
471100 | 1F | no | 1407.24
471101 | 1F | no | 1400
471102 | 1F | no | 1400
471103 | 1F | no | 1400
471104 | 1F | no | 1400
471105 | 1F | no | 1400
471106 | 1F | no | 1400
471107 | 1F | no | 1400
471108 | 1F | no | 1400
471109 | 1F | no | 1400
471110 | 1F | no | 1400
471111 | 1F | no | 1400
471112 | 1F | no | 1400
471113 | 1F | no | 1400
471114 | 1F | no | 1400
471115 | 1F | no | 1400
471116 | 1F | no | 1400
471117 | 1F | no | 1400
471118 | 1F | no | 1400
471119 | 1F | no | 1400
471120 | 1F | no | 1400
471121 | 1F | no | 585.308
471122 | 1F | no | 80.3155
471123 | 1F | no | 1400
471124 | 1F | no | 1400
471125 | 1F | no | 1400
471126 | 1F | no | 1400
471127 | 1F | no | 1400
471128 | 1F | no | 1400
471129 | 1F | no | 1400
471130 | 1F | no | 1400
471131 | 1F | no | 1400
471132 | 1F | no | 1400
471133 | 1F | no | 1400
471134 | 1F | no | 1400
471135 | 1F | no | 1400
471136 | 1F | no | 1400
471137 | 1F | no | 1400
471138 | 1F | no | 1400
471139 | 1F | no | 1400
471140 | 1F | no | 1400
471141 | 1F | no | 1400
471142 | 1F | no | 491.975
471143 | 1F | no | 1328.2
471144 | 1F | no | 1400
471145 | 1F | no | 1400
471146 | 1F | no | 1400
471147 | 1F | no | 1400
471148 | 1F | no | 1400
471149 | 1F | no | 1400
471150 | 1F | no | 1400
471151 | 1F | no | 1400
471152 | 1F | no | 1400
471153 | 1F | no | 1400
471154 | 1F | no | 1400
471155 | 1F | no | 1400
471156 | 1F | no | 1400
471157 | 1F | no | 1400
471158 | 1F | no | 1400
471159 | 1F | no | 398.642
471160 | 1F | no | 60.3148
471161 | 1F | no | 1400
471162 | 1F | no | 1400
471163 | 1F | no | 1400
471164 | 1F | no | 1400
471165 | 1F | no | 1400
471166 | 1F | no | 1348.2
471167 | 1F | no | 1325
471168 | 1F | no | 57.5042
471169 | 1F | no | 804.347
471170 | 1F | no | 1471.3
471171 | 1F | no | 2063.07
471172 | 1F | no | 483.562
471173 | 1F | no | 935.96
471174 | 1F | no | 1322.89
471175 | 1F | no | 1646.5
471176 | 1F | no | 1908.49
471177 | 1F | no | 152.694
471178 | 1F | no | 236.612
471179 | 1F | no | 262.379
471180 | 1F | no | 230.122
471181 | 1F | no | 139.683
471182 | 1F | no | 2090.62
471183 | 1F | no | 1882.21
471184 | 1F | no | 1613.4
471185 | 1F | no | 1282.81
471186 | 1F | no | 888.676
471187 | 1F | no | 2034.56
471188 | 1F | no | 1944.95
471189 | 1F | no | 1855.35
471190 | 1F | no | 1765.74
471191 | 1F | no | 1676.13
471192 | 1F | no | 1586.53
471193 | 1F | no | 1496.92
471194 | 1F | no | 1407.31
471195 | 1F | no | 1317.7
471196 | 1F | no | 1228.1
471197 | 1F | no | 1138.49
471198 | 1F | no | 1048.88
471199 | 1F | no | 959.274
471200 | 1F | no | 869.667
471201 | 1F | no | 780.06
471202 | 1F | no | 690.453
471203 | 1F | no | 600.845
471204 | 1F | no | 511.238
471205 | 1F | no | 421.631
471206 | 1F | no | 332.024
471207 | 1F | no | 242.416
471208 | 1F | no | 2100
471209 | 1F | no | 2100
471210 | 1F | no | 2100
471211 | 1F | no | 2100
471212 | 1F | no | 2100
471213 | 1F | no | 2100
471214 | 1F | no | 2100
471215 | 1F | no | 2100
471216 | 1F | no | 2100
471217 | 1F | no | 2100
471218 | 1F | no | 2100
471219 | 1F | no | 2100
471220 | 1F | no | 2100
471221 | 1F | no | 2100
471222 | 1F | no | 2100
471223 | 1F | no | 2100
471224 | 1F | no | 2100
471225 | 1F | no | 2100
471226 | 1F | no | 2100
471227 | 1F | no | 2100
471228 | 1F | no | 2100
471229 | 1F | no | 2100
471230 | 1F | no | 2100
471231 | 1F | no | 2100
471232 | 1F | no | 2100
471233 | 1F | no | 2100
471234 | 1F | no | 2100
471235 | 1F | no | 2100
471236 | 1F | no | 2100
471237 | 1F | no | 2100
471238 | 1F | no | 2100
471239 | 1F | no | 2100
471240 | 1F | no | 2100
471241 | 1F | no | 2100
471242 | 1F | no | 2100
471243 | 1F | no | 2100
471244 | 1F | no | 2100
471245 | 1F | no | 2100
471246 | 1F | no | 2100
471247 | 1F | no | 2100
471248 | 1F | no | 2100
471249 | 1F | no | 2100
471250 | 1F | no | 2100
471251 | 1F | no | 2100
471252 | 1F | no | 2100
471253 | 1F | no | 2100
471254 | 1F | no | 2100
471255 | 1F | no | 2100
471256 | 1F | no | 2100
471257 | 1F | no | 2100
471258 | 1F | no | 2100
471259 | 1F | no | 2100
471260 | 1F | no | 2100
471261 | 1F | no | 2100
471262 | 1F | no | 2100
471263 | 1F | no | 2100
471264 | 1F | no | 2100
471265 | 1F | no | 2100
471266 | 1F | no | 2100
471267 | 1F | no | 2100
471268 | 1F | no | 2100
471269 | 1F | no | 2100
471270 | 1F | no | 2100
471271 | 1F | no | 2100
471272 | 1F | no | 2100
471273 | 1F | no | 2100
471274 | 1F | no | 2100
471275 | 1F | no | 2100
471276 | 1F | no | 2100
471277 | 1F | no | 2100
471278 | 1F | no | 2100
471279 | 1F | no | 2100
471280 | 1F | no | 2100
471281 | 1F | no | 2100
471282 | 1F | no | 2100
471283 | 1F | no | 2100
471284 | 1F | no | 2100
471285 | 1F | no | 2100
471286 | 1F | no | 2100
471287 | 1F | no | 2100
471288 | 1F | no | 2100
471289 | 1F | no | 2100
471290 | 1F | no | 2100
471291 | 1F | no | 2100
471292 | 1F | no | 2100
471293 | 1F | no | 2100
471294 | 1F | no | 2100
471295 | 1F | no | 2100
471296 | 1F | no | 2100
471297 | 1F | no | 2100
471298 | 1F | no | 2100
471299 | 1F | no | 2100
471300 | 1F | no | 2100
471301 | 1F | no | 2100
471302 | 1F | no | 2100
471303 | 1F | no | 2100
471304 | 1F | no | 2100
471305 | 1F | no | 2100
471306 | 1F | no | 2100
471307 | 1F | no | 2125
471308 | 1F | no | 2100
471309 | 1F | no | 2100
471310 | 1F | no | 2100
471311 | 1F | no | 2100
471312 | 1F | no | 2100
470836 | 1F | no | 1275
470837 | 1F | no | 1400
470838 | 1F | no | 1400
470839 | 1F | no | 1400
470840 | 1F | no | 1400
470841 | 1F | no | 1400
470842 | 1F | no | 1400
470843 | 1F | no | 1400
470844 | 1F | no | 1400
470845 | 1F | no | 1400
470846 | 1F | no | 342.052
470847 | 1F | no | 1275
470848 | 1F | no | 1400
470849 | 1F | no | 1400
470850 | 1F | no | 1400
470851 | 1F | no | 1400
470852 | 1F | no | 1400
470853 | 1F | no | 1400
470854 | 1F | no | 1400
470855 | 1F | no | 1400
470856 | 1F | no | 1400
470857 | 1F | no | 147.438
470858 | 1F | no | 1275
470859 | 1F | no | 1400
470860 | 1F | no | 1400
470861 | 1F | no | 1400
470862 | 1F | no | 1400
470863 | 1F | no | 1400
470864 | 1F | no | 1400
470865 | 1F | no | 1400
470866 | 1F | no | 1400
470867 | 1F | no | 1270.57
470868 | 1F | no | 1275
470869 | 1F | no | 1400
470870 | 1F | no | 1400
470871 | 1F | no | 1400
470872 | 1F | no | 1400
470873 | 1F | no | 1400
470874 | 1F | no | 1400
470875 | 1F | no | 1400
470876 | 1F | no | 1400
470877 | 1F | no | 807.545
470878 | 1F | no | 1275
470879 | 1F | no | 1400
470880 | 1F | no | 1400
470881 | 1F | no | 1400
470882 | 1F | no | 1400
470883 | 1F | no | 1400
470884 | 1F | no | 1400
470885 | 1F | no | 1400
470886 | 1F | no | 1400
470887 | 1F | no | 202.528
470888 | 1F | no | 533.991
470889 | 1F | no | 1400
470890 | 1F | no | 1400
470891 | 1F | no | 1400
470892 | 1F | no | 1400
470893 | 1F | no | 1400
470894 | 1F | no | 1400
470895 | 1F | no | 1400
470896 | 1F | no | 897.407
470897 | 1F | no | 68.676
470898 | 1F | no | 1400
470899 | 1F | no | 1400
470900 | 1F | no | 1400
470901 | 1F | no | 1400
470902 | 1F | no | 1400
470903 | 1F | no | 1053.36
470904 | 1F | no | 1400
470905 | 1F | no | 338.873
470906 | 1F | no | 348.817
470907 | 1F | no | 1253.64
470908 | 1F | no | 58.455
470909 | 1F | no | 963.274
470910 | 1F | no | 1868.09
470911 | 1F | no | 672.912
470912 | 1F | no | 628.334
470913 | 1F | no | 679.747
470914 | 1F | no | 1212.87
470915 | 1F | no | 2100
470916 | 1F | no | 2100
470918 | 1F | no | 2100
470920 | 1F | no | 2100
470921 | 1F | no | 2100
470922 | 1F | no | 2100
470923 | 1F | no | 2100
470924 | 1F | no | 2100
470925 | 1F | no | 2100
470926 | 1F | no | 2100
470927 | 1F | no | 2125
470928 | 1F | no | 2100
470929 | 1F | no | 2125
470930 | 1F | no | 2100
470931 | 1F | no | 2100
470932 | 1F | no | 2100
470933 | 1F | no | 2100
470934 | 1F | no | 2100
470935 | 1F | no | 2100
470936 | 1F | no | 2100
470937 | 1F | no | 2100
470938 | 1F | no | 2100
470939 | 1F | no | 2100
470940 | 1F | no | 2100
470941 | 1F | no | 2100
470942 | 1F | no | 2100
470943 | 1F | no | 2100
470944 | 1F | no | 2100
470945 | 1F | no | 2100
470946 | 1F | no | 2100
470947 | 1F | no | 2100
470948 | 1F | no | 2100
470949 | 1F | no | 2100
470950 | 1F | no | 2100
470951 | 1F | no | 2100
470952 | 1F | no | 2100
470953 | 1F | no | 2100
470954 | 1F | no | 2100
470955 | 1F | no | 2100
470956 | 1F | no | 2100
470957 | 1F | no | 2100
470958 | 1F | no | 2100
470959 | 1F | no | 2100
470960 | 1F | no | 2100
470961 | 1F | no | 2100
470962 | 1F | no | 2100
470963 | 1F | no | 2100
470964 | 1F | no | 2100
470965 | 1F | no | 2100
470966 | 1F | no | 2100
470967 | 1F | no | 2100
470968 | 1F | no | 2100
470969 | 1F | no | 2100
470970 | 1F | no | 2100
470971 | 1F | no | 2100
470972 | 1F | no | 2100
470973 | 1F | no | 2100
470974 | 1F | no | 2100
470975 | 1F | no | 2125
470976 | 1F | no | 2100
470977 | 1F | no | 2100
471313 | 1F | no | 1353.71
471314 | 1F | no | 1400
471315 | 1F | no | 1119.2
471316 | 1F | no | 330.803
471317 | 1F | no | 1400
471319 | 1F | no | 1138.84
471320 | 1F | no | 1400
471321 | 1F | no | 1119.2
471322 | 1F | no | 330.803
471323 | 1F | no | 1400
471325 | 1F | no | 777.34
471326 | 1F | no | 1400
471327 | 1F | no | 1119.2
471328 | 1F | no | 330.803
471329 | 1F | no | 1400
471331 | 1F | no | 263.875
471332 | 1F | no | 1400
471333 | 1F | no | 1119.2
471334 | 1F | no | 330.803
471335 | 1F | no | 1400
471337 | 1F | no | 1040.41
471338 | 1F | no | 1119.2
471339 | 1F | no | 330.803
471340 | 1F | no | 1400
471342 | 1F | no | 195.521
471343 | 1F | no | 1400
471344 | 1F | no | 1400
471345 | 1F | no | 1400
471346 | 1F | no | 1400
471347 | 1F | no | 503.546
471348 | 1F | no | 613.266
471349 | 1F | no | 1400
471350 | 1F | no | 38.2318
471351 | 1F | no | 964.599
471352 | 1F | no | 483.823
471353 | 1F | no | 944.276
471354 | 1F | no | 39.4575
471355 | 1F | no | 1234.64
471356 | 1F | no | 329.82
471357 | 1F | no | 1525
471358 | 1F | no | 620.182
471359 | 1F | no | 2100
471360 | 1F | no | 2100
471361 | 1F | no | 2100
471362 | 1F | no | 2100
471363 | 1F | no | 2100
471364 | 1F | no | 2100
471365 | 1F | no | 2100
471366 | 1F | no | 2100
471367 | 1F | no | 2100
471368 | 1F | no | 2100
471369 | 1F | no | 2100
471370 | 1F | no | 2100
471371 | 1F | no | 2100
471372 | 1F | no | 2100
471373 | 1F | no | 2100
471374 | 1F | no | 2100
471375 | 1F | no | 2100
471376 | 1F | no | 2100
471377 | 1F | no | 2100
471378 | 1F | no | 2100
471379 | 1F | no | 1600
471380 | 1F | no | 1600
471381 | 1F | no | 1600
471382 | 1F | no | 1600
471383 | 1F | no | 2100
471384 | 1F | no | 2100
472101 | 1F | no | 1356.32
472102 | 1F | no | 1400
472103 | 1F | no | 728.431
472104 | 1F | no | 479.478
472105 | 1F | no | 1400
472106 | 1F | no | 1400
472107 | 1F | no | 1400
472108 | 1F | no | 1400
472109 | 1F | no | 1153.22
472110 | 1F | no | 114.271
472111 | 1F | no | 1400
472112 | 1F | no | 1400
472113 | 1F | no | 1400
472114 | 1F | no | 1400
472115 | 1F | no | 1400
472116 | 1F | no | 1400
472117 | 1F | no | 1400
472118 | 1F | no | 1400
472119 | 1F | no | 1400
472120 | 1F | no | 1400
472121 | 1F | no | 1400
472122 | 1F | no | 1400
472123 | 1F | no | 1400
472124 | 1F | no | 64.3336
472125 | 1F | no | 141.886
472126 | 1F | no | 1400
472127 | 1F | no | 1400
472128 | 1F | no | 1400
472129 | 1F | no | 1400
472130 | 1F | no | 1400
472131 | 1F | no | 1400
472132 | 1F | no | 1400
472133 | 1F | no | 1400
472134 | 1F | no | 1400
472135 | 1F | no | 1410.91
472136 | 1F | no | 166.098
472137 | 1F | no | 1400
472138 | 1F | no | 1400
472139 | 1F | no | 1400
472140 | 1F | no | 1400
472141 | 1F | no | 1307.5
472142 | 1F | no | 357.381
472143 | 1F | no | 1315.72
472144 | 1F | no | 79.0121
472145 | 1F | no | 854.818
472146 | 1F | no | 1549.27
472147 | 1F | no | 67.3932
472148 | 1F | no | 613.293
472149 | 1F | no | 1090.37
472150 | 1F | no | 1501.42
472151 | 1F | no | 1848.72
472152 | 1F | no | 34.1297
472153 | 1F | no | 259.116
472154 | 1F | no | 424.801
472155 | 1F | no | 531.996
472156 | 1F | no | 581.217
472157 | 1F | no | 1813.98
472158 | 1F | no | 1266.53
472159 | 1F | no | 410.033
472160 | 1F | no | 2100
472161 | 1F | no | 2100
472162 | 1F | no | 1741.16
472163 | 1F | no | 1053.78
472164 | 1F | no | 442.902
472165 | 1F | no | 2100
472166 | 1F | no | 2100
472167 | 1F | no | 2100
472168 | 1F | no | 2004.42
472169 | 1F | no | 1534.96
472170 | 1F | no | 1131.74
472171 | 1F | no | 792.495
472172 | 1F | no | 515.405
472173 | 1F | no | 299.026
472174 | 1F | no | 142.264
472175 | 1F | no | 44.342
472176 | 1F | no | 100.269
472177 | 1F | no | 2100
472178 | 1F | no | 2100
472179 | 1F | no | 2100
472180 | 1F | no | 2100
472181 | 1F | no | 2100
472182 | 1F | no | 2100
472183 | 1F | no | 2100
472184 | 1F | no | 2100
472185 | 1F | no | 2125
472186 | 1F | no | 2125
472187 | 1F | no | 2100
472188 | 1F | no | 2100
472189 | 1F | no | 2100
472190 | 1F | no | 2100
472191 | 1F | no | 2100
472058 | 1F | no | 84.3653
472059 | 1F | no | 1400
472060 | 1F | no | 1400
472061 | 1F | no | 1400
472062 | 1F | no | 614.437
472063 | 1F | no | 269.091
472064 | 1F | no | 1400
472065 | 1F | no | 1400
472066 | 1F | no | 1400
472067 | 1F | no | 431.727
472068 | 1F | no | 579.11
472069 | 1F | no | 1400
472070 | 1F | no | 1400
472071 | 1F | no | 1400
472072 | 1F | no | 125.141
472073 | 1F | no | 1017.75
472074 | 1F | no | 1400
472075 | 1F | no | 1400
472076 | 1F | no | 1141.46
472077 | 1F | no | 1344.31
472078 | 1F | no | 1400
472079 | 1F | no | 575.921
472080 | 1F | no | 2070.67
472081 | 1F | no | 497.706
472082 | 1F | no | 1024.74
472083 | 1F | no | 800.683
472084 | 1F | no | 2100
472085 | 1F | no | 2100
472086 | 1F | no | 2100
472087 | 1F | no | 2100
472088 | 1F | no | 2100
472089 | 1F | no | 2100
472090 | 1F | no | 2100
472091 | 1F | no | 2100
472092 | 1F | no | 2100
472093 | 1F | no | 2100
472094 | 1F | no | 2100
472095 | 1F | no | 2100
472096 | 1F | no | 2100
472097 | 1F | no | 2100
472098 | 1F | no | 2100
472099 | 1F | no | 2100
472100 | 1F | no | 2100
472018 | 1F | no | 1351.25
472019 | 1F | no | 1400
472020 | 1F | no | 820.907
472021 | 1F | no | 1128.9
472022 | 1F | no | 1400
472023 | 1F | no | 1035.77
472024 | 1F | no | 754.572
472025 | 1F | no | 1400
472026 | 1F | no | 1397.26
472027 | 1F | no | 222.315
472028 | 1F | no | 1400
472029 | 1F | no | 174.506
472030 | 1F | no | 608.635
472031 | 1F | no | 72.5146
472032 | 1F | no | 1513.45
472033 | 1F | no | 2100
472034 | 1F | no | 2100
472035 | 1F | no | 2100
472036 | 1F | no | 2100
472037 | 1F | no | 2100
472038 | 1F | no | 2100
472039 | 1F | no | 2100
472040 | 1F | no | 2100
473396 | 3F | no | 1414.91
473397 | 3F | no | 1400
473398 | 3F | no | 1400
473399 | 3F | no | 1400
473400 | 3F | no | 1400
473401 | 3F | no | 1400
473402 | 3F | no | 1400
473403 | 3F | no | 1400
473404 | 3F | no | 1400
473405 | 3F | no | 1400
473406 | 3F | no | 1400
473407 | 3F | no | 1400
473408 | 3F | no | 1400
473409 | 3F | no | 1400
473410 | 3F | no | 1400
473411 | 3F | no | 1400
473412 | 3F | no | 1400
473413 | 3F | no | 1400
473414 | 3F | no | 1400
473415 | 3F | no | 1400
473416 | 3F | no | 1400
473417 | 3F | no | 577.637
473418 | 3F | no | 227.451
473419 | 3F | no | 156.103
473420 | 3F | no | 100.832
473421 | 3F | no | 61.3069
473422 | 3F | no | 37.5166
473423 | 3F | no | 29.4554
473424 | 3F | no | 37.1211
473425 | 3F | no | 60.5157
473426 | 3F | no | 99.6452
473427 | 3F | no | 154.519
473428 | 3F | no | 225.152
473429 | 3F | no | 311.562
473430 | 3F | no | 413.771
473431 | 3F | no | 531.804
473432 | 3F | no | 665.692
473433 | 3F | no | 815.471
473434 | 3F | no | 981.177
473435 | 3F | no | 1162.85
473436 | 3F | no | 1360.55
473437 | 3F | no | 1574.31
473438 | 3F | no | 1804.21
473439 | 3F | no | 2050.28
473440 | 3F | no | 2100
473441 | 3F | no | 2100
473442 | 3F | no | 2100
473443 | 3F | no | 2100
473444 | 3F | no | 2100
473445 | 3F | no | 2100
473446 | 3F | no | 2100
473447 | 3F | no | 2100
473448 | 3F | no | 2100
473449 | 3F | no | 2100
473450 | 3F | no | 2100
473451 | 3F | no | 2100
473452 | 3F | no | 2100
473453 | 3F | no | 2100
473454 | 3F | no | 2100
473455 | 3F | no | 2100
473456 | 3F | no | 2100
473457 | 3F | no | 2100
473458 | 3F | no | 2100
473459 | 3F | no | 2100
473460 | 3F | no | 2100

# IfcMember: 50 x 150mm (238)
Type - ElementType: 50 x 150mm; PredefinedType: MEMBER
Material: 金属 - 铝
Pset_MemberCommon - LoadBearing: yes; Reference: 50 x 150mm
Name (矩形竖梃:50 x 150mm:...) | In | IsExternal | Span (mm)
402187 | 1F | yes | 3069.02
402192 | 1F | yes | 3069.02
402197 | 1F | yes | 550
402198 | 1F | yes | 450
529689 | 1F | yes | 500
529690 | 1F | yes | 550
529914 | 1F | yes | 500
529915 | 1F | yes | 500
529916 | 1F | yes | 500
529917 | 1F | yes | 500
529918 | 1F | yes | 500
529919 | 1F | yes | 500
529920 | 1F | yes | 500
529921 | 1F | yes | 450
402450 | 1F | yes | 4460
402455 | 1F | yes | 4460
402460 | 1F | yes | 550
402461 | 1F | yes | 450
529691 | 1F | yes | 500
529692 | 1F | yes | 550
529922 | 1F | yes | 500
529923 | 1F | yes | 500
529924 | 1F | yes | 500
529925 | 1F | yes | 500
529926 | 1F | yes | 500
529927 | 1F | yes | 500
529928 | 1F | yes | 500
529929 | 1F | yes | 450
402660 | 1F | yes | 2460
402661 | 1F | yes | 2460
402662 | 1F | yes | 3000
402663 | 1F | yes | 3000
402854 | 1F | yes | 3860
402855 | 1F | yes | 3860
402856 | 1F | yes | 3000
402857 | 1F | yes | 3000
403016 | 1F | yes | 2460
403017 | 1F | yes | 2460
403018 | 1F | yes | 3000
403019 | 1F | yes | 3000
407616 | 2F | yes | 3069.02
407621 | 2F | yes | 550
407622 | 2F | yes | 350
431910 | 2F | yes | 3069.02
529693 | 2F | yes | 500
529694 | 2F | yes | 550
529930 | 2F | yes | 500
529931 | 2F | yes | 500
529932 | 2F | yes | 500
529933 | 2F | yes | 500
529934 | 2F | yes | 500
529935 | 2F | yes | 500
529936 | 2F | yes | 500
529937 | 2F | yes | 350
407642 | 2F | yes | 4460
407647 | 2F | yes | 550
407648 | 2F | yes | 350
431915 | 2F | yes | 4460
529695 | 2F | yes | 500
529696 | 2F | yes | 550
529938 | 2F | yes | 500
529939 | 2F | yes | 500
529940 | 2F | yes | 500
529941 | 2F | yes | 500
529942 | 2F | yes | 500
529943 | 2F | yes | 500
529944 | 2F | yes | 500
529945 | 2F | yes | 350
407661 | 3F | yes | 2065
407663 | 3F | yes | 2700
407664 | 3F | yes | 2700
435360 | 3F | yes | 1745
407667 | 3F | yes | 2460
407669 | 3F | yes | 2700
407670 | 3F | yes | 2700
408705 | 2F | yes | 1660
408706 | 2F | yes | 1710
408707 | 2F | yes | 2500
408708 | 2F | yes | 2450
531046 | 3F | yes | 1290
427614 | 3F | yes | 2860
427619 | 3F | yes | 2860
427624 | 3F | yes | 550
427625 | 3F | yes | 250
529697 | 3F | yes | 500
529698 | 3F | yes | 550
529946 | 3F | yes | 500
529947 | 3F | yes | 500
529948 | 3F | yes | 500
529949 | 3F | yes | 500
529950 | 3F | yes | 500
529951 | 3F | yes | 250
427914 | 3F | no | 1100
427916 | 3F | no | 2075
427917 | 3F | no | 625
427918 | 3F | no | 625
427919 | 3F | no | 2075
428389 | 3F | no | 1400
428391 | 3F | no | 2075
428392 | 3F | no | 625
428393 | 3F | no | 625
428394 | 3F | no | 2075
428792 | 3F | no | 1100
428794 | 3F | no | 2075
428795 | 3F | no | 625
428796 | 3F | no | 625
428797 | 3F | no | 2075
429211 | 3F | no | 1100
429213 | 3F | no | 2075
429214 | 3F | no | 625
429215 | 3F | no | 625
429216 | 3F | no | 2075
429512 | 3F | no | 1400
429514 | 3F | no | 2075
429515 | 3F | no | 625
429516 | 3F | no | 625
429517 | 3F | no | 2075
429932 | 2F | no | 1900
429933 | 2F | no | 1900
429934 | 2F | no | 2125
429935 | 2F | no | 575
429936 | 2F | no | 575
429937 | 2F | no | 2125
430073 | 2F | no | 3200
430074 | 2F | no | 3200
430075 | 2F | no | 2125
430076 | 2F | no | 575
430077 | 2F | no | 575
430078 | 2F | no | 2125
430240 | 2F | no | 2100
430241 | 2F | no | 2100
430242 | 2F | no | 2125
430243 | 2F | no | 575
430244 | 2F | no | 575
430245 | 2F | no | 2125
432703 | 1F | yes | 2860
432708 | 1F | yes | 2860
432713 | 1F | yes | 550
432718 | 1F | yes | 250
529303 | 1F | yes | 500
529305 | 1F | yes | 550
529699 | 1F | yes | 500
529700 | 1F | yes | 500
529952 | 1F | yes | 500
529953 | 1F | yes | 500
529954 | 1F | yes | 500
529955 | 1F | yes | 500
529956 | 1F | yes | 500
529957 | 1F | yes | 500
529958 | 1F | yes | 500
529959 | 1F | yes | 500
529960 | 1F | yes | 500
529961 | 1F | yes | 500
529962 | 1F | yes | 500
529963 | 1F | yes | 250
432955 | 1F | yes | 1180
432956 | 1F | yes | 1180
432957 | 1F | yes | 875
432958 | 1F | yes | 850
432959 | 1F | yes | 850
432960 | 1F | yes | 850
432961 | 1F | yes | 875
432962 | 1F | yes | 875
432963 | 1F | yes | 875
432964 | 1F | yes | 850
432965 | 1F | yes | 850
432966 | 1F | yes | 850
434042 | 1F | yes | 2180
434044 | 1F | yes | 2600
434045 | 1F | yes | 2600
434842 | -1F | yes | 6500
434847 | -1F | yes | 6500
434852 | -1F | yes | 550
434853 | -1F | yes | 450
529701 | -1F | yes | 500
529702 | -1F | yes | 550
529964 | -1F | yes | 500
529965 | -1F | yes | 500
529966 | -1F | yes | 500
529967 | -1F | yes | 500
529968 | -1F | yes | 500
529969 | -1F | yes | 450
563198 | -1F | yes | 1366.36
563199 | -1F | yes | 1396.36
563200 | -1F | yes | 1396.36
563201 | -1F | yes | 1396.36
563202 | -1F | yes | 1396.36
563203 | -1F | yes | 1396.36
563204 | -1F | yes | 1396.36
563205 | -1F | yes | 1396.36
563206 | -1F | yes | 1396.36
563207 | -1F | yes | 1396.36
437521 | -1F | yes | 15380
437526 | -1F | yes | 15380
437531 | -1F | yes | 500
437532 | -1F | yes | 500
438284 | 2F | yes | 1300
438286 | 2F | yes | 900
438287 | 2F | yes | 1650
438499 | 2F | yes | 860
438888 | 2F | yes | 1650
438889 | 2F | yes | 900
439301 | 2F | yes | 785
439422 | 3F | yes | 1260
439423 | 3F | yes | 900
439424 | 3F | yes | 1650
439427 | 3F | yes | 860
439432 | 3F | yes | 1650
439433 | 3F | yes | 900
439435 | 3F | yes | 785
439497 | 3F | yes | 1660
439498 | 3F | yes | 1660
439499 | 3F | yes | 2500
439500 | 3F | yes | 2500
488587 | 1F | yes | 870
488588 | 1F | yes | 810
488589 | 1F | yes | 950
488590 | 1F | yes | 950
500217 | 1F | yes | 860
500218 | 1F | yes | 1170
500283 | 1F | yes | 1170
500284 | 1F | yes | 920
488949 | 1F | yes | 440
488950 | 1F | yes | 430
488951 | 1F | yes | 1000
488952 | 1F | yes | 1000
488955 | 1F | yes | 430
488956 | 1F | yes | 480
488964 | 1F | yes | 480
488967 | 1F | yes | 440
528990 | 4F | yes | 152.025
528995 | 4F | yes | 387.883
529705 | 4F | yes | 522.18
529706 | 4F | yes | 1874.65
529976 | 4F | yes | 1664.53
529977 | 4F | yes | 152.025
529978 | 4F | yes | 522.18
529979 | 4F | yes | 387.883

# IfcPlate: 玻璃 (561)
Type - ElementType: 玻璃; PredefinedType: CURTAIN_PANEL; Material: <Unnamed> 30 mm
Pset_PlateCommon - Reference: 玻璃; LoadBearing: yes
Name (系统嵌板:玻璃:...) | In | IsExternal
362913 | 1F | no
363073 | 1F | no
362933 | 1F | no
362934 | 1F | no
363066 | 1F | no
363074 | 1F | no
362936 | 1F | no
362937 | 1F | no
480462 | 1F | no
363075 | 1F | no
362939 | 1F | no
362940 | 1F | no
363068 | 1F | no
363076 | 1F | no
362942 | 1F | no
362943 | 1F | no
363069 | 1F | no
362912 | 1F | no
362917 | 1F | no
363010 | 1F | no
362919 | 1F | no
362920 | 1F | no
363011 | 1F | no
362922 | 1F | no
362923 | 1F | no
363012 | 1F | no
362925 | 1F | no
362926 | 1F | no
363013 | 1F | no
366783 | 3F | no
366790 | 3F | no
366810 | 3F | no
366811 | 3F | no
366812 | 3F | no
366813 | 3F | no
366822 | 3F | no
366823 | 3F | no
366824 | 3F | no
366825 | 3F | no
366826 | 3F | no
366827 | 3F | no
366828 | 3F | no
366829 | 3F | no
366836 | 3F | no
366837 | 3F | no
366838 | 3F | no
366839 | 3F | no
366840 | 3F | no
366841 | 3F | no
366842 | 3F | no
366843 | 3F | no
366844 | 3F | no
366850 | 3F | no
366851 | 3F | no
366852 | 3F | no
366853 | 3F | no
366854 | 3F | no
366855 | 3F | no
366856 | 3F | no
366866 | 3F | no
366867 | 3F | no
366868 | 3F | no
370760 | 1F | no
370767 | 1F | no
370769 | 1F | no
370770 | 1F | no
370772 | 1F | no
370773 | 1F | no
370775 | 1F | no
370776 | 1F | no
370778 | 1F | no
370779 | 1F | no
370958 | 1F | no
370967 | 1F | no
371075 | 1F | no
370969 | 1F | no
370971 | 1F | no
371076 | 1F | no
370973 | 1F | no
370975 | 1F | no
371077 | 1F | no
370977 | 1F | no
370979 | 1F | no
371078 | 1F | no
370981 | 1F | no
370983 | 1F | no
371079 | 1F | no
370985 | 1F | no
370987 | 1F | no
371080 | 1F | no
402176 | 1F | yes
529639 | 1F | yes
529812 | 1F | yes
529814 | 1F | yes
529816 | 1F | yes
529818 | 1F | yes
402437 | 1F | yes
529641 | 1F | yes
529820 | 1F | yes
529822 | 1F | yes
529824 | 1F | yes
529826 | 1F | yes
402657 | 1F | yes
402851 | 1F | yes
403014 | 1F | yes
407602 | 2F | yes
529643 | 2F | yes
529828 | 2F | yes
529830 | 2F | yes
529832 | 2F | yes
529834 | 2F | yes
407628 | 2F | yes
529645 | 2F | yes
529836 | 2F | yes
529838 | 2F | yes
529840 | 2F | yes
529842 | 2F | yes
408703 | 2F | yes
530605 | 3F | yes
531015 | 3F | yes
530642 | 3F | yes
530990 | 3F | yes
531003 | 3F | yes
531016 | 3F | yes
427602 | 3F | yes
529647 | 3F | yes
529844 | 3F | yes
529846 | 3F | yes
529848 | 3F | yes
427911 | 3F | no
428386 | 3F | no
428789 | 3F | no
429208 | 3F | no
429511 | 3F | no
429926 | 2F | no
429929 | 2F | no
430067 | 2F | no
430070 | 2F | no
430234 | 2F | no
430237 | 2F | no
432667 | 1F | yes
529145 | 1F | yes
529649 | 1F | yes
529850 | 1F | yes
529852 | 1F | yes
529854 | 1F | yes
529856 | 1F | yes
529858 | 1F | yes
529860 | 1F | yes
432944 | 1F | yes
432947 | 1F | yes
432949 | 1F | yes
432951 | 1F | yes
432953 | 1F | yes
434831 | -1F | yes
529651 | -1F | yes
529862 | -1F | yes
529864 | -1F | yes
529866 | -1F | yes
437508 | -1F | yes
438281 | 2F | yes
438877 | 2F | yes
439421 | 3F | yes
439430 | 3F | yes
439496 | 3F | yes
470214 | 1F | no
470322 | 1F | no
470324 | 1F | no
470326 | 1F | no
470328 | 1F | no
470330 | 1F | no
470332 | 1F | no
470334 | 1F | no
470336 | 1F | no
470338 | 1F | no
470340 | 1F | no
470342 | 1F | no
470344 | 1F | no
470346 | 1F | no
470348 | 1F | no
470350 | 1F | no
470352 | 1F | no
470354 | 1F | no
470356 | 1F | no
470358 | 1F | no
470360 | 1F | no
470362 | 1F | no
470364 | 1F | no
470365 | 1F | no
470366 | 1F | no
470367 | 1F | no
470368 | 1F | no
470369 | 1F | no
470370 | 1F | no
470371 | 1F | no
470372 | 1F | no
470373 | 1F | no
470374 | 1F | no
470375 | 1F | no
470376 | 1F | no
470377 | 1F | no
470378 | 1F | no
470379 | 1F | no
470380 | 1F | no
470381 | 1F | no
470382 | 1F | no
470383 | 1F | no
470384 | 1F | no
470385 | 1F | no
470387 | 1F | no
470388 | 1F | no
470389 | 1F | no
470390 | 1F | no
470391 | 1F | no
470392 | 1F | no
470393 | 1F | no
470394 | 1F | no
470395 | 1F | no
470396 | 1F | no
470397 | 1F | no
470398 | 1F | no
470399 | 1F | no
470400 | 1F | no
470401 | 1F | no
470402 | 1F | no
470403 | 1F | no
470404 | 1F | no
470405 | 1F | no
470406 | 1F | no
470407 | 1F | no
470408 | 1F | no
470410 | 1F | no
470411 | 1F | no
470412 | 1F | no
470413 | 1F | no
470414 | 1F | no
470415 | 1F | no
470416 | 1F | no
470417 | 1F | no
470418 | 1F | no
470419 | 1F | no
470420 | 1F | no
470421 | 1F | no
470422 | 1F | no
470423 | 1F | no
470424 | 1F | no
470425 | 1F | no
470426 | 1F | no
470427 | 1F | no
470428 | 1F | no
470429 | 1F | no
470430 | 1F | no
470431 | 1F | no
470433 | 1F | no
470434 | 1F | no
470435 | 1F | no
470436 | 1F | no
470437 | 1F | no
470438 | 1F | no
470439 | 1F | no
470440 | 1F | no
470441 | 1F | no
470442 | 1F | no
470443 | 1F | no
470444 | 1F | no
470445 | 1F | no
470446 | 1F | no
470447 | 1F | no
470448 | 1F | no
470449 | 1F | no
470450 | 1F | no
470451 | 1F | no
470452 | 1F | no
470453 | 1F | no
470454 | 1F | no
470458 | 1F | no
470459 | 1F | no
470460 | 1F | no
470461 | 1F | no
470462 | 1F | no
470463 | 1F | no
470464 | 1F | no
470465 | 1F | no
470466 | 1F | no
470467 | 1F | no
470468 | 1F | no
470469 | 1F | no
470470 | 1F | no
470471 | 1F | no
470472 | 1F | no
470473 | 1F | no
470474 | 1F | no
470475 | 1F | no
470476 | 1F | no
470477 | 1F | no
470484 | 1F | no
470485 | 1F | no
470486 | 1F | no
470487 | 1F | no
470488 | 1F | no
470489 | 1F | no
470490 | 1F | no
470491 | 1F | no
470492 | 1F | no
470493 | 1F | no
470494 | 1F | no
470495 | 1F | no
470496 | 1F | no
470497 | 1F | no
470498 | 1F | no
470499 | 1F | no
470500 | 1F | no
470514 | 1F | no
470515 | 1F | no
470516 | 1F | no
470517 | 1F | no
470215 | 1F | no
470525 | 1F | no
470535 | 1F | no
470537 | 1F | no
470539 | 1F | no
470541 | 1F | no
470543 | 1F | no
470545 | 1F | no
470546 | 1F | no
470547 | 1F | no
470548 | 1F | no
470549 | 1F | no
470550 | 1F | no
470551 | 1F | no
470552 | 1F | no
470553 | 1F | no
470554 | 1F | no
470555 | 1F | no
470557 | 1F | no
470558 | 1F | no
470559 | 1F | no
470560 | 1F | no
470561 | 1F | no
470562 | 1F | no
470563 | 1F | no
470564 | 1F | no
470565 | 1F | no
470566 | 1F | no
470569 | 1F | no
470570 | 1F | no
470571 | 1F | no
470572 | 1F | no
470573 | 1F | no
470574 | 1F | no
470575 | 1F | no
470576 | 1F | no
470577 | 1F | no
470578 | 1F | no
470581 | 1F | no
470582 | 1F | no
470583 | 1F | no
470584 | 1F | no
470585 | 1F | no
470586 | 1F | no
470587 | 1F | no
470588 | 1F | no
470589 | 1F | no
470590 | 1F | no
470593 | 1F | no
470594 | 1F | no
470595 | 1F | no
470596 | 1F | no
470597 | 1F | no
470598 | 1F | no
470599 | 1F | no
470600 | 1F | no
470601 | 1F | no
470602 | 1F | no
470605 | 1F | no
470606 | 1F | no
470607 | 1F | no
470608 | 1F | no
470609 | 1F | no
470610 | 1F | no
470611 | 1F | no
470612 | 1F | no
470613 | 1F | no
470620 | 1F | no
470621 | 1F | no
470622 | 1F | no
470623 | 1F | no
470624 | 1F | no | Material: 玻璃
470625 | 1F | no
470634 | 1F | no
470635 | 1F | no
470636 | 1F | no
470213 | 1F | no
470236 | 1F | no
470238 | 1F | no
470246 | 1F | no
470248 | 1F | no
470252 | 1F | no
470253 | 1F | no
470254 | 1F | no
470258 | 1F | no
470259 | 1F | no
470262 | 1F | no
470263 | 1F | no
470264 | 1F | no
470268 | 1F | no
470269 | 1F | no
470272 | 1F | no
470273 | 1F | no
470274 | 1F | no
470278 | 1F | no
470279 | 1F | no
470282 | 1F | no
470283 | 1F | no
470284 | 1F | no
470288 | 1F | no
470289 | 1F | no
470293 | 1F | no
470294 | 1F | no
470295 | 1F | no
470296 | 1F | no
470297 | 1F | no
470298 | 1F | no
470299 | 1F | no
470300 | 1F | no
470303 | 1F | no
470304 | 1F | no
470305 | 1F | no
470306 | 1F | no
470307 | 1F | no
470308 | 1F | no
470314 | 1F | no
470315 | 1F | no
471676 | 1F | no
471695 | 1F | no
471697 | 1F | no
471727 | 1F | no
471728 | 1F | no
471729 | 1F | no
471730 | 1F | no
471731 | 1F | no
471732 | 1F | no
471745 | 1F | no
471746 | 1F | no
471747 | 1F | no
471748 | 1F | no
471749 | 1F | no
471750 | 1F | no
471751 | 1F | no
471752 | 1F | no
471753 | 1F | no
471754 | 1F | no
471755 | 1F | no
471756 | 1F | no
471766 | 1F | no
471767 | 1F | no
471768 | 1F | no
471769 | 1F | no
471770 | 1F | no
471771 | 1F | no
471772 | 1F | no
471773 | 1F | no
471774 | 1F | no
471775 | 1F | no
471776 | 1F | no
471777 | 1F | no
471778 | 1F | no
471787 | 1F | no
471788 | 1F | no
471789 | 1F | no
471790 | 1F | no
471791 | 1F | no
471792 | 1F | no
471793 | 1F | no
471794 | 1F | no
471795 | 1F | no
471796 | 1F | no
471810 | 1F | no
471811 | 1F | no
471812 | 1F | no
471813 | 1F | no
471814 | 1F | no
471817 | 1F | no
471821 | 1F | no
471823 | 1F | no
471825 | 1F | no
471826 | 1F | no
471827 | 1F | no
471828 | 1F | no
471829 | 1F | no
471831 | 1F | no
471832 | 1F | no
471833 | 1F | no
471834 | 1F | no
471835 | 1F | no
471837 | 1F | no
471838 | 1F | no
471839 | 1F | no
471840 | 1F | no
471843 | 1F | no
471844 | 1F | no
471845 | 1F | no
471846 | 1F | no
471850 | 1F | no
471851 | 1F | no
471852 | 1F | no
471678 | 1F | no
471855 | 1F | no
471857 | 1F | no
471861 | 1F | no
471862 | 1F | no
471863 | 1F | no
471866 | 1F | no
471867 | 1F | no
471868 | 1F | no
471871 | 1F | no
471872 | 1F | no
471873 | 1F | no
471874 | 1F | no
471876 | 1F | no
471877 | 1F | no
473226 | 3F | no
473233 | 3F | no
473235 | 3F | no
473237 | 3F | no
473239 | 3F | no
473241 | 3F | no
473243 | 3F | no
473245 | 3F | no
473247 | 3F | no
473249 | 3F | no
473251 | 3F | no
473253 | 3F | no
473255 | 3F | no
473257 | 3F | no
473259 | 3F | no
473261 | 3F | no
473263 | 3F | no
473265 | 3F | no
473267 | 3F | no
473269 | 3F | no
473271 | 3F | no
473273 | 3F | no
473275 | 3F | no
473284 | 3F | no
473285 | 3F | no
473286 | 3F | no
473287 | 3F | no
473288 | 3F | no
473289 | 3F | no
473290 | 3F | no
473291 | 3F | no
473292 | 3F | no
473293 | 3F | no
473294 | 3F | no
473295 | 3F | no
473296 | 3F | no
528401 | 4F | yes
529655 | 4F | yes
529874 | 4F | yes
529876 | 4F | yes

# IfcPlate: 玻璃嵌板 (20)
Type - ElementType: 玻璃嵌板; PredefinedType: CURTAIN_PANEL; Material: 玻璃
Pset_PlateCommon - IsExternal: yes; LoadBearing: yes; Reference: 玻璃嵌板
Name (玻璃嵌板:玻璃嵌板:...) | In
437168 | -1F
563174 | -1F
563176 | -1F
563178 | -1F
563184 | -1F
563186 | -1F
563188 | -1F
563190 | -1F
563192 | -1F
488585 | 1F
500211 | 1F
500276 | 1F
488809 | 1F
490172 | 1F
490177 | 1F
490182 | 1F
490187 | 1F
488948 | 1F
488954 | 1F
488959 | 1F

# IfcRailing: 栏杆扶手:900mm (5)
Material: 不锈钢
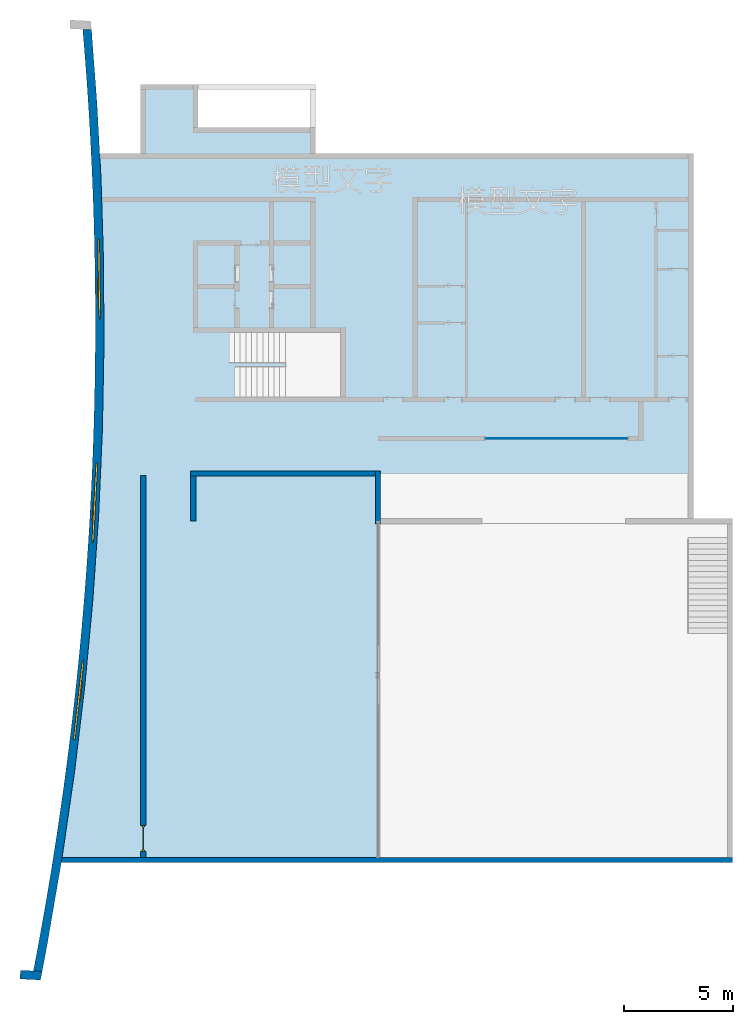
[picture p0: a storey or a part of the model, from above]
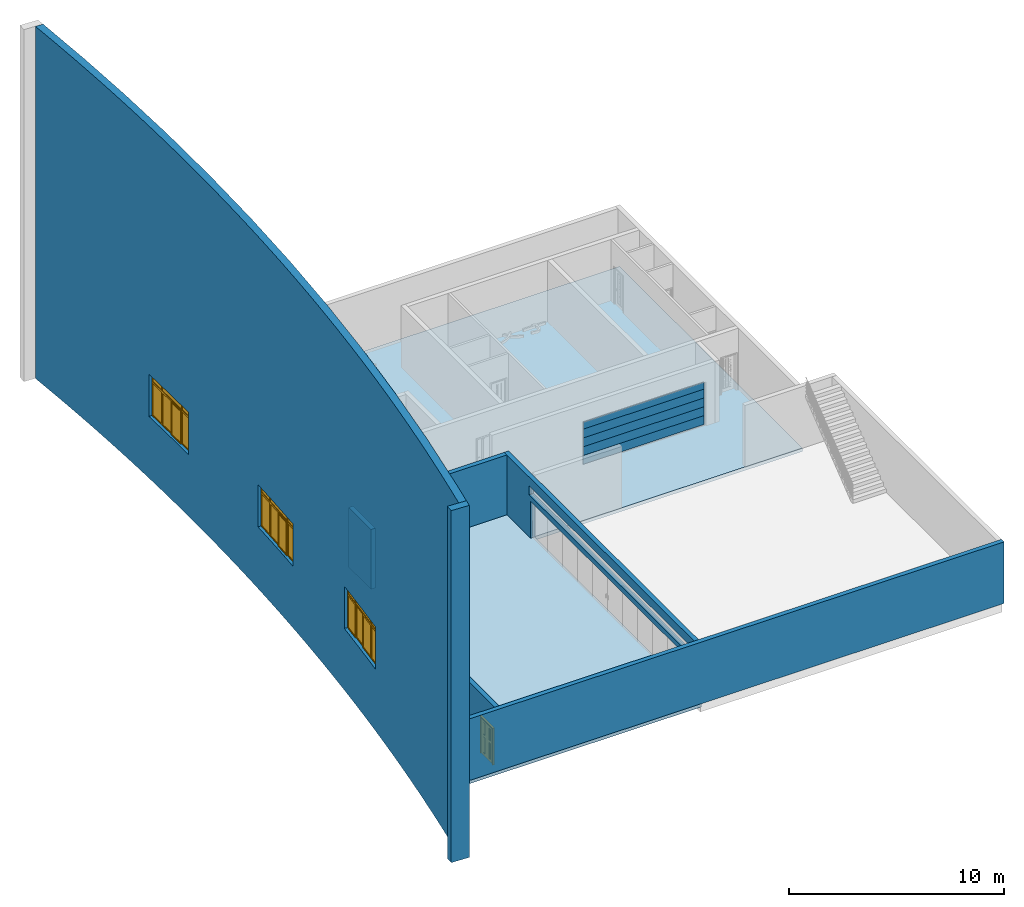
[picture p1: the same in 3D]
Properties of the parts of a building model (IFC2X3), part 2 of 2

# IfcRailing: 栏杆扶手:900mm (5)
Pset_RailingCommon - IsExternal: no; Reference: 900mm; Height: 1219.2 mm
Name (栏杆扶手:900mm:...) | In
414902 | 2F
415247 | 3F
441685 | -1F
442968 | 1F
443215 | 2F

# IfcRailing: 栏杆扶手:900mm 圆管 (21)
Material: 不锈钢
Pset_RailingCommon - IsExternal: no; Reference: 900mm 圆管; Height: 1219.2 mm
Name (栏杆扶手:900mm 圆管:...) | In
450859 | 2F
457113 | 2F
457334 | 2F
457524 | 3F
457725 | 3F
457778 | 3F
457794 | 3F
457814 | 3F
457830 | 3F
479544 | 4F
492467 | 1F
492841 | -1F
493455 | 1F
494227 | 1F
498246 | 1F
530227 | 1F
531133 | 2F
531336 | 3F
531349 | 1F
532271 | 4F
534170 | 2F

# IfcRoof: 基本屋顶:白屋顶 (8)
Pset_RoofCommon - IsExternal: yes; Reference: 白屋顶
Name (基本屋顶:白屋顶:...) | In | TotalArea (m2) | ProjectedArea (m2)
474485 | 4F | 2.7816 | 2.7816
475005 | 4F | 84.24 | 84.24
478742 | 2F | 44.6424 | 44.6424
481677 | 3F | 9.0816 | 9.0816
530140 | 2F | 9.0816 | 9.0816
532201 | 1F | 9.0816 | 9.0816
534342 | 3F | 9.091 | 4.5455
535032 | 4F | 5.24869 | 4.5455

# IfcRoof: 基本屋顶:白屋顶:371983, 基本屋顶:白屋顶:475266
In: 4F
Pset_RoofCommon - IsExternal: yes; Reference: 白屋顶; TotalArea: 221.094 m2; ProjectedArea: 221.094 m2

# IfcRoof: 玻璃斜窗:玻璃斜窗, 玻璃斜窗:玻璃斜窗:488804
In: 1F
Pset_RoofCommon - IsExternal: yes; Reference: 玻璃斜窗; ProjectedArea: 46 m2

# IfcRoof: 玻璃斜窗:玻璃斜窗 2 (2)
In: 1F
Pset_RoofCommon - IsExternal: yes; Reference: 玻璃斜窗 2
Name (玻璃斜窗:玻璃斜窗 2:...) | ProjectedArea (m2)
488012 | 2.95
488943 | 1.45

# IfcSlab: 基本屋顶:白屋顶 (8)
PredefinedType: ROOF; Material: 白色涂料 10 mm, 默认屋顶 80 mm, 白色涂料 10 mm
Pset_SlabCommon - IsExternal: yes; Reference: 白屋顶
Name (基本屋顶:白屋顶:...) | In | PitchAngle (deg)
474485 | 4F | 0
475005 | 4F | 0
478742 | 2F | 0
481677 | 3F | 0
530140 | 2F | 0
532201 | 1F | 0
534342 | 3F | 60
535032 | 4F | 30

# IfcSlab: 基本屋顶:白屋顶:371983, 基本屋顶:白屋顶:475266:1
In: 4F
PredefinedType: ROOF; Material: 白色涂料; 白色涂料 10 mm, 默认屋顶 80 mm, 白色涂料 10 mm
Pset_SlabCommon - IsExternal: yes; PitchAngle: 0 deg; Reference: 白屋顶

# IfcSlab: 建筑地坪:建筑地坪 1, 建筑地坪:建筑地坪 1:545492
In: 室外地坪
PredefinedType: FLOOR; Material: <Unnamed> 300 mm
Pset_SlabCommon - IsExternal: no; Reference: 建筑地坪 1

# IfcSlab: 楼板:室外广场 (2)
PredefinedType: FLOOR
Pset_SlabCommon - LoadBearing: no; IsExternal: no; Reference: 室外广场
Name (楼板:室外广场:...) | In | Material
491475 | -1F | 石材, 默认楼板
542691 | 室外地坪 | 石材 20 mm, 默认楼板 430 mm

# IfcSlab: 楼板:常规 - 100mm (9)
PredefinedType: FLOOR; Material: 默认楼板 100 mm
Pset_SlabCommon - LoadBearing: no; IsExternal: no; Reference: 常规 - 100mm
Name (楼板:常规 - 100mm:...) | In | PitchAngle (deg)
404680 | 1F
413473 | 2F
414814 | 2F | 0
415240 | 3F | 0
430270 | 3F | 0
430795 | 3F
496654 | 1F | 0
497004 | 2F | 0
497022 | 4F | 0

# IfcSlab: 楼板:常规 - 200mm, 楼板:常规 - 200mm:387623
In: -1F
PredefinedType: FLOOR; Material: 混凝土，现场浇注 - C30 200 mm
Pset_SlabCommon - LoadBearing: no; IsExternal: no; Reference: 常规 - 200mm; ThermalTransmittance: 5.23 kg/K/s3; PitchAngle: 0 deg

# IfcSlab: 楼梯:整体式楼梯:55159, 楼梯:整体式楼梯:440708:1
In: -1F
PredefinedType: LANDING; Material: 混凝土 - 现场浇注
Pset_SlabCommon - IsExternal: no; Reference: 整体式楼梯

# IfcStair: 楼梯:室外楼梯:230177 (3)
Pset_StairCommon - IsExternal: no; Reference: 室外楼梯; TreadLength: 260 mm
Name (楼梯:室外楼梯:...) | In | NumberOfRiser | NumberOfTreads | RiserHeight (mm)
492796 | -1F | 18 | 17 | 205.556
498038 | 1F | 16 | 15 | 150
534139 | 2F | 16 | 15 | 187.5

# IfcStair: 楼梯:整体式楼梯:55159 (3)
Pset_StairCommon - IsExternal: no; Reference: 整体式楼梯; TreadLength: 260 mm
Name (楼梯:整体式楼梯:...) | In | NumberOfRiser = NumberOfTreads | RiserHeight (mm)
440708 | -1F | 20 | 175
442930 | 1F | 21 | 142.857
443177 | 2F | 21 | 142.857

# IfcStairFlight: 楼梯:室外楼梯:230177 (3)
TreadLength: 0.853018 mm
Pset_StairFlightCommon - Reference: 室外楼梯; TreadLength: 260 mm; TreadLengthAtOffset: 260 mm; NosingLength: 260 mm
Name (楼梯:室外楼梯:...) | In | NumberOfRiser | NumberOfTreads | RiserHeight (mm) | Pset_StairFlightCommon, NumberOfRiser | Pset_StairFlightCommon, NumberOfTreads | Pset_StairFlightCommon, RiserHeight (mm) | WalkingLineOffset (mm) | WaistThickness (mm)
492796:1 | -1F | 18 | 17 | 0.674395 | 18 | 17 | 205.556 | 900 | 1800
498038:1 | 1F | 8 | 7 | 0.492126 | 16 | 15 | 150 | 280 | 560
534139:1 | 2F | 8 | 7 | 0.615157 | 16 | 15 | 187.5 | 280 | 560

# IfcStairFlight: 楼梯:整体式楼梯:55159 (2)
NumberOfRiser: 11; NumberOfTreads: 10; RiserHeight: 0.468691 mm; TreadLength: 0.853018 mm; Material: 混凝土 - 现场浇注
Pset_StairFlightCommon - Reference: 整体式楼梯; NumberOfRiser: 21; NumberOfTreads: 21; RiserHeight: 142.857 mm; TreadLength: 260 mm; TreadLengthAtOffset: 260 mm; NosingLength: 260 mm; WalkingLineOffset: 700 mm; WaistThickness: 1400 mm
Name (楼梯:整体式楼梯:...) | In
442930:1 | 1F
443177:1 | 2F

# IfcWall: 基本墙:石墙 - 400mm (3)
In: 1F
Type - Material: 石灰华 20 mm, 混凝土，现场浇注 - C40 360 mm, 石灰华 20 mm
Pset_WallCommon - Reference: 石墙 - 400mm; LoadBearing: no; ExtendToStructure: no; IsExternal: yes; ThermalTransmittance: 2.7936 kg/K/s3
Name (基本墙:石墙 - 400mm:...)
362786 | Material: 石灰华 (2), 混凝土，现场浇注 - C40
362787
362788

# IfcWall: 基本墙:粉刷墙240 (3)
Type - PredefinedType: STANDARD; Material: 白色涂料 10 mm, 默认墙 220 mm, 白色涂料 10 mm
Pset_WallCommon - LoadBearing: no; IsExternal: yes; Reference: 粉刷墙240
Name (基本墙:粉刷墙240:...) | In | ExtendToStructure
393706 | 1F | no
407577 | 2F | yes
536885 | 4F | no

# IfcWallStandardCase: 基本墙:内墙240, 基本墙:内墙240:503436
In: 2F
Type - PredefinedType: STANDARD; Material: 木质 - 木材 20 mm, 默认墙 200 mm, 木质 - 木材 20 mm
Pset_WallCommon - LoadBearing: no; ExtendToStructure: no; IsExternal: yes; Reference: 内墙240

# IfcWallStandardCase: 基本墙:内墙450 (2)
In: 1F
Type - PredefinedType: STANDARD; Material: 木质 - 木材 20 mm, 默认墙 410 mm, 木质 - 木材 20 mm
Pset_WallCommon - LoadBearing: no; ExtendToStructure: no; IsExternal: yes; Reference: 内墙450
Name (基本墙:内墙450:...)
501506
502795

# IfcWallStandardCase: 基本墙:石墙 - 400mm (4)
Type - Material: 石灰华 20 mm, 混凝土，现场浇注 - C40 360 mm, 石灰华 20 mm
Pset_WallCommon - Reference: 石墙 - 400mm; LoadBearing: no; ExtendToStructure: no; IsExternal: yes; ThermalTransmittance: 2.7936 kg/K/s3
Name (基本墙:石墙 - 400mm:...) | In
362789 | -1F
362790 | -1F
362791 | 1F
362811 | -1F

# IfcWallStandardCase: 基本墙:粉刷墙120 (26)
Type - PredefinedType: STANDARD; Material: 白色涂料 10 mm, 默认墙 100 mm, 白色涂料 10 mm
Pset_WallCommon - LoadBearing: no; ExtendToStructure: no; IsExternal: yes; Reference: 粉刷墙120
Name (基本墙:粉刷墙120:...) | In
381257 | -1F
381380 | -1F
381420 | -1F
381534 | -1F
381617 | -1F
381657 | -1F
381711 | -1F
421148 | 3F
421194 | 3F
421286 | 3F
421533 | 3F
421648 | 3F
421903 | 3F
422367 | 3F
422462 | 3F
422549 | 3F
422694 | 3F
422776 | 3F
422897 | 3F
423039 | 3F
423429 | 3F
423588 | 3F
423629 | 3F
423738 | 3F
423822 | 3F
424010 | 3F

# IfcWallStandardCase: 基本墙:粉刷墙240 (158)
Type - PredefinedType: STANDARD; Material: 白色涂料 10 mm, 默认墙 220 mm, 白色涂料 10 mm
Pset_WallCommon - LoadBearing: no; IsExternal: yes; Reference: 粉刷墙240
Name (基本墙:粉刷墙240:...) | In | ExtendToStructure
376209 | -1F | no
376727 | -1F | no
376766 | -1F | no
377204 | -1F | no
377472 | -1F | no
377631 | -1F | no
377806 | -1F | no
377995 | -1F | yes
378164 | -1F | yes
378695 | -1F | no
378870 | -1F | no
379071 | -1F | no
379266 | -1F | no
379423 | -1F | no
379524 | -1F | no
379583 | -1F | yes
379900 | -1F | yes
379970 | -1F | yes
380069 | -1F | yes
380221 | -1F | yes
380263 | -1F | yes
380386 | -1F | yes
380577 | -1F | yes
380630 | -1F | yes
380777 | -1F | yes
380826 | -1F | yes
390925 | 1F | no
391195 | 1F | no
391317 | 1F | no
391478 | 1F | no
391613 | 1F | no
391781 | 1F | no
391875 | 1F | no
392029 | 1F | no
392131 | 1F | yes
392132 | 1F | no
392133 | 1F | no
392134 | 1F | no
392135 | 1F | no
392136 | 1F | no
392137 | 1F | no
392138 | 1F | no
392139 | 1F | no
392140 | 1F | no
392773 | 1F | no
392824 | 1F | no
392933 | 1F | no
393098 | 1F | no
393261 | 1F | no
393455 | 1F | no
393828 | 1F | no
393897 | 1F | no
394028 | 1F | no
394118 | 1F | no
394152 | 1F | no
394229 | 1F | no
394371 | 1F | no
394589 | 1F | no
394678 | 1F | no
394729 | 1F | no
394785 | 1F | no
394902 | 1F | no
394950 | 1F | no
395016 | 1F | no
395497 | 1F | no
395596 | 1F | no
395658 | 1F | no
395703 | 1F | no
395896 | 1F | no
396030 | 1F | no
396178 | 1F | no
407561 | 2F | yes
407562 | 2F | yes
407563 | 2F | no
407564 | 2F | yes
407565 | 2F | yes
407566 | 2F | yes
407567 | 2F | yes
407568 | 2F | yes
407569 | 2F | yes
407570 | 2F | yes
407572 | 2F | yes
407573 | 2F | no
407574 | 2F | yes
407575 | 2F | no
407576 | 2F | yes
407578 | 2F | yes
407579 | 2F | yes
407580 | 2F | yes
407581 | 2F | yes
407582 | 2F | yes
407583 | 2F | yes
407584 | 2F | no
407585 | 2F | yes
407586 | 2F | yes
407587 | 2F | yes
407591 | 2F | yes
415615 | 3F | no
415758 | 3F | no
416045 | 3F | no
416113 | 3F | no
416166 | 3F | no
416239 | 3F | no
416607 | 3F | no
416925 | 3F | no
417320 | 3F | no
417423 | 3F | no
417546 | 3F | no
417653 | 3F | no
417972 | 3F | no
418331 | 1F | no
418788 | 3F | no
418894 | 3F | no
418982 | 3F | no
419500 | 3F | no
419602 | 3F | no
420015 | 3F | no
420061 | 3F | no
420172 | 3F | no
420237 | 3F | no
420324 | 4F | no
420389 | 3F | no
420628 | 3F | no
426809 | 3F | no
439920 | 2F | no
451233 | 1F | no
458101 | 3F | no
458212 | 3F | no
458289 | 3F | no
474019 | 4F | no
476711 | 4F | no
476755 | 4F | no
477688 | 4F | no
478984 | 4F | no
481552 | 2F | no
481627 | 2F | no
491906 | -1F | no
496085 | -1F | no
496127 | -1F | no
496187 | -1F | no
496236 | -1F | no
496295 | -1F | no
504619 | 2F | no
504789 | 2F | no
505435 | 1F | no
505538 | 2F | no
507265 | 2F | no
507308 | 2F | no
507446 | 4F | no
507528 | 4F | no
515621 | 4F | no
515704 | 4F | no
530136 | 1F | no
530137 | 1F | no
532145 | -1F | no
532146 | -1F | no
537209 | 1F | no
537452 | 3F | no

# IfcWallStandardCase: 基本墙:粉刷墙450, 基本墙:粉刷墙450:504146
In: 1F
Type - PredefinedType: STANDARD; Material: 白色涂料 10 mm, 默认墙 430 mm, 白色涂料 10 mm
Pset_WallCommon - LoadBearing: no; ExtendToStructure: no; IsExternal: yes; Reference: 粉刷墙450

# IfcWindow: C0505 (5)
Type - ParameterTakesPrecedence: no; Sizeable: no; Material: 竖梃, 玻璃
OverallHeight: 500 mm; OverallWidth: 500 mm
Pset_WindowCommon - IsExternal: yes; Reference: C0505
Name (C0615:C0505:...) | In
399516 | 1F
426268 | 3F
536994 | 3F
537151 | 2F
537153 | 2F

# IfcWindow: C0915 (6)
Type - ParameterTakesPrecedence: no; Sizeable: no; Material: 玻璃, 竖梃
OverallHeight: 1500 mm; OverallWidth: 900 mm
Pset_WindowCommon - IsExternal: yes; Reference: C0915
Name (C0915:C0915:...) | In
497206 | 1F
497253 | 1F
497442 | 2F
497443 | 2F
497447 | 3F
497448 | 3F

# IfcWindow: C0923 (2)
Type - ParameterTakesPrecedence: no; Sizeable: no; Material: 竖梃, 玻璃
OverallHeight: 2300 mm; OverallWidth: 900 mm
Pset_WindowCommon - IsExternal: yes; Reference: C0923
Name (C0615:C0923:...) | In
409989 | 2F
426853 | 3F

# IfcWindow: C1223, C0615:C1223:426023
In: 3F
Type - ParameterTakesPrecedence: no; Sizeable: no; Material: 竖梃, 玻璃
OverallHeight: 2300 mm; OverallWidth: 1160 mm
Pset_WindowCommon - IsExternal: yes; Reference: C1223

# IfcWindow: C1313, 转角窗:C1313:401151
In: 1F
Type - ParameterTakesPrecedence: no; Sizeable: no; Material: 玻璃, 铝
OverallHeight: 2000 mm; OverallWidth: 2120 mm
Pset_WindowCommon - IsExternal: yes; Reference: C1313

# IfcWindow: C1326 (2)
Type - ParameterTakesPrecedence: no; Sizeable: no; Material: 玻璃, 铝
OverallHeight: 2000 mm; OverallWidth: 2700 mm
Pset_WindowCommon - IsExternal: yes; Reference: C1326
Name (转角窗:C1326:...) | In
407600 | 2F
426864 | 3F
